# Copyright (c) 1993 - 2026 ARM Limited. All Rights Reserved.
# Use of this Software is subject to the terms and conditions of the
# applicable license agreement with ARM Limited.

# PhyVGen V 11.0.0-beta2
# ARM Version r0p0
# Creation Date: Tue Apr  7 18:10:24 2026


# Memory Configuration:
# ~~~~~~~~~~~~~~~~~~~~~
#  -activity_factor 50 -atf off -back_biasing off -bits 64 -bmux off
# -bus_notation on -check_instname on -diodes on -drive 6 -ema on -frequency
# 1.0 -instname rf64x64 -left_bus_delim "[" -mux 2 -mvt BASE -name_case lower
# -power_gating off -power_type otc -pwr_gnd_rename
# vddpe:VDDPE,vddce:VDDCE,vsse:VSSE -rcols 2 -redundancy off -retention on
# -right_bus_delim "]" -rrows 0 -ser none -site_def off -top_layer m5-m10
# -vmin_assist off -words 64 -wp_size 1 -write_mask on -write_thru off
# 

VERSION 5.8 ;
BUSBITCHARS "[]" ;
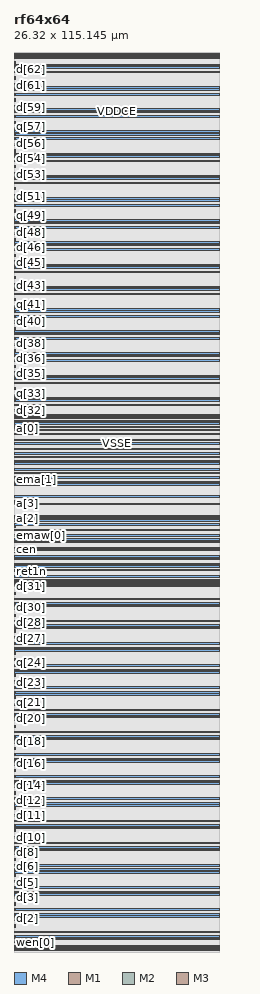
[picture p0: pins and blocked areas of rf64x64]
MACRO rf64x64
	FOREIGN rf64x64 0 0 ;
	SYMMETRY X Y ;
	SIZE 26.32 BY 115.145 ;
	CLASS BLOCK ;
	PIN VDDCE
		USE POWER ;
		DIRECTION INOUT ;
		PORT
			LAYER	M4 ;
			RECT	0 50.525 26.32 50.735 ;
		END

		PORT
			LAYER	M4 ;
			RECT	0 62.375 26.32 62.585 ;
		END

		PORT
			LAYER	M4 ;
			RECT	0 64.235 26.32 64.385 ;
		END

		PORT
			LAYER	M4 ;
			RECT	0 67.84 26.32 67.99 ;
		END

		PORT
			LAYER	M4 ;
			RECT	0 113.045 26.32 113.255 ;
		END

		PORT
			LAYER	M4 ;
			RECT	0 44.49 26.32 44.7 ;
		END

		PORT
			LAYER	M4 ;
			RECT	0 41.65 26.32 41.86 ;
		END

		PORT
			LAYER	M4 ;
			RECT	0 38.81 26.32 39.02 ;
		END

		PORT
			LAYER	M4 ;
			RECT	0 107.365 26.32 107.575 ;
		END

		PORT
			LAYER	M4 ;
			RECT	0 35.97 26.32 36.18 ;
		END

		PORT
			LAYER	M4 ;
			RECT	0 33.13 26.32 33.34 ;
		END

		PORT
			LAYER	M4 ;
			RECT	0 30.29 26.32 30.5 ;
		END

		PORT
			LAYER	M4 ;
			RECT	0 27.45 26.32 27.66 ;
		END

		PORT
			LAYER	M4 ;
			RECT	0 24.61 26.32 24.82 ;
		END

		PORT
			LAYER	M4 ;
			RECT	0 21.77 26.32 21.98 ;
		END

		PORT
			LAYER	M4 ;
			RECT	0 18.93 26.32 19.14 ;
		END

		PORT
			LAYER	M4 ;
			RECT	0 16.09 26.32 16.3 ;
		END

		PORT
			LAYER	M4 ;
			RECT	0 13.25 26.32 13.46 ;
		END

		PORT
			LAYER	M4 ;
			RECT	0 10.41 26.32 10.62 ;
		END

		PORT
			LAYER	M4 ;
			RECT	0 104.525 26.32 104.735 ;
		END

		PORT
			LAYER	M4 ;
			RECT	0 7.57 26.32 7.78 ;
		END

		PORT
			LAYER	M4 ;
			RECT	0 4.73 26.32 4.94 ;
		END

		PORT
			LAYER	M4 ;
			RECT	0 1.89 26.32 2.1 ;
		END

		PORT
			LAYER	M4 ;
			RECT	0 101.685 26.32 101.895 ;
		END

		PORT
			LAYER	M4 ;
			RECT	0 98.845 26.32 99.055 ;
		END

		PORT
			LAYER	M4 ;
			RECT	0 96.005 26.32 96.215 ;
		END

		PORT
			LAYER	M4 ;
			RECT	0 93.165 26.32 93.375 ;
		END

		PORT
			LAYER	M4 ;
			RECT	0 90.325 26.32 90.535 ;
		END

		PORT
			LAYER	M4 ;
			RECT	0 87.485 26.32 87.695 ;
		END

		PORT
			LAYER	M4 ;
			RECT	0 84.645 26.32 84.855 ;
		END

		PORT
			LAYER	M4 ;
			RECT	0 81.805 26.32 82.015 ;
		END

		PORT
			LAYER	M4 ;
			RECT	0 78.965 26.32 79.175 ;
		END

		PORT
			LAYER	M4 ;
			RECT	0 76.125 26.32 76.335 ;
		END

		PORT
			LAYER	M4 ;
			RECT	0 73.285 26.32 73.495 ;
		END

		PORT
			LAYER	M4 ;
			RECT	0 70.445 26.32 70.655 ;
		END

		PORT
			LAYER	M4 ;
			RECT	0 110.205 26.32 110.415 ;
		END

		PORT
			LAYER	M4 ;
			RECT	0 46.795 26.32 46.925 ;
		END

		PORT
			LAYER	M4 ;
			RECT	0 50.225 26.32 50.355 ;
		END

		PORT
			LAYER	M4 ;
			RECT	0 114.325 26.32 114.475 ;
		END

		PORT
			LAYER	M4 ;
			RECT	0 62.755 26.32 62.885 ;
		END

		PORT
			LAYER	M4 ;
			RECT	0 0.67 26.32 0.82 ;
		END

		PORT
			LAYER	M4 ;
			RECT	0 68.63 26.32 68.76 ;
		END

	END VDDCE

	PIN VDDPE
		USE POWER ;
		DIRECTION INOUT ;
		PORT
			LAYER	M4 ;
			RECT	0 48.815 26.32 48.965 ;
		END

		PORT
			LAYER	M4 ;
			RECT	0 49.185 26.32 49.395 ;
		END

		PORT
			LAYER	M4 ;
			RECT	0 52.71 26.32 52.92 ;
		END

		PORT
			LAYER	M4 ;
			RECT	0 53.185 26.32 53.395 ;
		END

		PORT
			LAYER	M4 ;
			RECT	0 54.6 26.32 54.81 ;
		END

		PORT
			LAYER	M4 ;
			RECT	0 55.745 26.32 55.895 ;
		END

		PORT
			LAYER	M4 ;
			RECT	0 58.16 26.32 58.37 ;
		END

		PORT
			LAYER	M4 ;
			RECT	0 59.72 26.32 59.93 ;
		END

		PORT
			LAYER	M4 ;
			RECT	0 60.58 26.32 60.79 ;
		END

		PORT
			LAYER	M4 ;
			RECT	0 63.69 26.32 63.9 ;
		END

		PORT
			LAYER	M4 ;
			RECT	0 66.67 26.32 66.88 ;
		END

		PORT
			LAYER	M4 ;
			RECT	0 67.045 26.32 67.255 ;
		END

		PORT
			LAYER	M4 ;
			RECT	0 112.465 26.32 112.675 ;
		END

		PORT
			LAYER	M4 ;
			RECT	0 45.07 26.32 45.28 ;
		END

		PORT
			LAYER	M4 ;
			RECT	0 42.23 26.32 42.44 ;
		END

		PORT
			LAYER	M4 ;
			RECT	0 39.39 26.32 39.6 ;
		END

		PORT
			LAYER	M4 ;
			RECT	0 36.55 26.32 36.76 ;
		END

		PORT
			LAYER	M4 ;
			RECT	0 33.71 26.32 33.92 ;
		END

		PORT
			LAYER	M4 ;
			RECT	0 106.785 26.32 106.995 ;
		END

		PORT
			LAYER	M4 ;
			RECT	0 30.87 26.32 31.08 ;
		END

		PORT
			LAYER	M4 ;
			RECT	0 28.03 26.32 28.24 ;
		END

		PORT
			LAYER	M4 ;
			RECT	0 25.19 26.32 25.4 ;
		END

		PORT
			LAYER	M4 ;
			RECT	0 22.35 26.32 22.56 ;
		END

		PORT
			LAYER	M4 ;
			RECT	0 19.51 26.32 19.72 ;
		END

		PORT
			LAYER	M4 ;
			RECT	0 16.67 26.32 16.88 ;
		END

		PORT
			LAYER	M4 ;
			RECT	0 13.83 26.32 14.04 ;
		END

		PORT
			LAYER	M4 ;
			RECT	0 10.99 26.32 11.2 ;
		END

		PORT
			LAYER	M4 ;
			RECT	0 8.15 26.32 8.36 ;
		END

		PORT
			LAYER	M4 ;
			RECT	0 5.31 26.32 5.52 ;
		END

		PORT
			LAYER	M4 ;
			RECT	0 103.945 26.32 104.155 ;
		END

		PORT
			LAYER	M4 ;
			RECT	0 2.47 26.32 2.68 ;
		END

		PORT
			LAYER	M4 ;
			RECT	0 101.105 26.32 101.315 ;
		END

		PORT
			LAYER	M4 ;
			RECT	0 98.265 26.32 98.475 ;
		END

		PORT
			LAYER	M4 ;
			RECT	0 95.425 26.32 95.635 ;
		END

		PORT
			LAYER	M4 ;
			RECT	0 92.585 26.32 92.795 ;
		END

		PORT
			LAYER	M4 ;
			RECT	0 89.745 26.32 89.955 ;
		END

		PORT
			LAYER	M4 ;
			RECT	0 86.905 26.32 87.115 ;
		END

		PORT
			LAYER	M4 ;
			RECT	0 84.065 26.32 84.275 ;
		END

		PORT
			LAYER	M4 ;
			RECT	0 81.225 26.32 81.435 ;
		END

		PORT
			LAYER	M4 ;
			RECT	0 78.385 26.32 78.595 ;
		END

		PORT
			LAYER	M4 ;
			RECT	0 75.545 26.32 75.755 ;
		END

		PORT
			LAYER	M4 ;
			RECT	0 72.705 26.32 72.915 ;
		END

		PORT
			LAYER	M4 ;
			RECT	0 69.865 26.32 70.075 ;
		END

		PORT
			LAYER	M4 ;
			RECT	0 109.625 26.32 109.835 ;
		END

		PORT
			LAYER	M4 ;
			RECT	0 114.825 26.32 114.975 ;
		END

		PORT
			LAYER	M4 ;
			RECT	0 47.215 26.32 47.345 ;
		END

		PORT
			LAYER	M4 ;
			RECT	0 51.685 26.32 51.815 ;
		END

		PORT
			LAYER	M4 ;
			RECT	0 0.17 26.32 0.32 ;
		END

		PORT
			LAYER	M4 ;
			RECT	0 60.06 26.32 60.19 ;
		END

		PORT
			LAYER	M4 ;
			RECT	0 68.21 26.32 68.34 ;
		END

	END VDDPE

	PIN VSSE
		USE GROUND ;
		DIRECTION INOUT ;
		PORT
			LAYER	M4 ;
			RECT	0 47.005 26.32 47.135 ;
		END

		PORT
			LAYER	M4 ;
			RECT	0 114.575 26.32 114.725 ;
		END

		PORT
			LAYER	M4 ;
			RECT	0 53.985 26.32 54.115 ;
		END

		PORT
			LAYER	M4 ;
			RECT	0 0.42 26.32 0.57 ;
		END

		PORT
			LAYER	M4 ;
			RECT	0 61.25 26.32 61.38 ;
		END

		PORT
			LAYER	M4 ;
			RECT	0 65.445 26.32 65.575 ;
		END

		PORT
			LAYER	M4 ;
			RECT	0 68.42 26.32 68.55 ;
		END

		PORT
			LAYER	M4 ;
			RECT	0 47.54 26.32 47.67 ;
		END

		PORT
			LAYER	M4 ;
			RECT	0 47.95 26.32 48.16 ;
		END

		PORT
			LAYER	M4 ;
			RECT	0 49.53 26.32 49.74 ;
		END

		PORT
			LAYER	M4 ;
			RECT	0 51.32 26.32 51.47 ;
		END

		PORT
			LAYER	M4 ;
			RECT	0 52.425 26.32 52.575 ;
		END

		PORT
			LAYER	M4 ;
			RECT	0 55.135 26.32 55.285 ;
		END

		PORT
			LAYER	M4 ;
			RECT	0 55.475 26.32 55.625 ;
		END

		PORT
			LAYER	M4 ;
			RECT	0 57.19 26.32 57.4 ;
		END

		PORT
			LAYER	M4 ;
			RECT	0 61.61 26.32 61.82 ;
		END

		PORT
			LAYER	M4 ;
			RECT	0 63.215 26.32 63.425 ;
		END

		PORT
			LAYER	M4 ;
			RECT	0 64.955 26.32 65.165 ;
		END

		PORT
			LAYER	M4 ;
			RECT	0 66.15 26.32 66.36 ;
		END

		PORT
			LAYER	M4 ;
			RECT	0 67.515 26.32 67.725 ;
		END

		PORT
			LAYER	M4 ;
			RECT	0 113.355 26.32 113.565 ;
		END

		PORT
			LAYER	M4 ;
			RECT	0 107.675 26.32 107.885 ;
		END

		PORT
			LAYER	M4 ;
			RECT	0 44.18 26.32 44.39 ;
		END

		PORT
			LAYER	M4 ;
			RECT	0 41.34 26.32 41.55 ;
		END

		PORT
			LAYER	M4 ;
			RECT	0 38.5 26.32 38.71 ;
		END

		PORT
			LAYER	M4 ;
			RECT	0 35.66 26.32 35.87 ;
		END

		PORT
			LAYER	M4 ;
			RECT	0 32.82 26.32 33.03 ;
		END

		PORT
			LAYER	M4 ;
			RECT	0 29.98 26.32 30.19 ;
		END

		PORT
			LAYER	M4 ;
			RECT	0 27.14 26.32 27.35 ;
		END

		PORT
			LAYER	M4 ;
			RECT	0 24.3 26.32 24.51 ;
		END

		PORT
			LAYER	M4 ;
			RECT	0 21.46 26.32 21.67 ;
		END

		PORT
			LAYER	M4 ;
			RECT	0 18.62 26.32 18.83 ;
		END

		PORT
			LAYER	M4 ;
			RECT	0 104.835 26.32 105.045 ;
		END

		PORT
			LAYER	M4 ;
			RECT	0 15.78 26.32 15.99 ;
		END

		PORT
			LAYER	M4 ;
			RECT	0 12.94 26.32 13.15 ;
		END

		PORT
			LAYER	M4 ;
			RECT	0 10.1 26.32 10.31 ;
		END

		PORT
			LAYER	M4 ;
			RECT	0 7.26 26.32 7.47 ;
		END

		PORT
			LAYER	M4 ;
			RECT	0 4.42 26.32 4.63 ;
		END

		PORT
			LAYER	M4 ;
			RECT	0 1.58 26.32 1.79 ;
		END

		PORT
			LAYER	M4 ;
			RECT	0 101.995 26.32 102.205 ;
		END

		PORT
			LAYER	M4 ;
			RECT	0 99.155 26.32 99.365 ;
		END

		PORT
			LAYER	M4 ;
			RECT	0 96.315 26.32 96.525 ;
		END

		PORT
			LAYER	M4 ;
			RECT	0 93.475 26.32 93.685 ;
		END

		PORT
			LAYER	M4 ;
			RECT	0 90.635 26.32 90.845 ;
		END

		PORT
			LAYER	M4 ;
			RECT	0 87.795 26.32 88.005 ;
		END

		PORT
			LAYER	M4 ;
			RECT	0 84.955 26.32 85.165 ;
		END

		PORT
			LAYER	M4 ;
			RECT	0 82.115 26.32 82.325 ;
		END

		PORT
			LAYER	M4 ;
			RECT	0 79.275 26.32 79.485 ;
		END

		PORT
			LAYER	M4 ;
			RECT	0 76.435 26.32 76.645 ;
		END

		PORT
			LAYER	M4 ;
			RECT	0 73.595 26.32 73.805 ;
		END

		PORT
			LAYER	M4 ;
			RECT	0 70.755 26.32 70.965 ;
		END

		PORT
			LAYER	M4 ;
			RECT	0 110.515 26.32 110.725 ;
		END

	END VSSE

	PIN a[0]
		USE SIGNAL ;
		DIRECTION INPUT ;
		SHAPE ABUTMENT ;
		PORT
			LAYER	M1 ;
			RECT	0 66.945 0.25 67.045 ;
			LAYER	M2 ;
			RECT	0 66.945 0.25 67.045 ;
			LAYER	M3 ;
			RECT	0 66.945 0.25 67.045 ;
		END

		ANTENNAGATEAREA 0.014 ;
		ANTENNADIFFAREA 0.018 ;
		ANTENNAPARTIALMETALAREA 0.025 ;
	END a[0]

	PIN a[1]
		USE SIGNAL ;
		DIRECTION INPUT ;
		SHAPE ABUTMENT ;
		PORT
			LAYER	M1 ;
			RECT	0 55.05 0.25 55.15 ;
			LAYER	M2 ;
			RECT	0 55.05 0.25 55.15 ;
			LAYER	M3 ;
			RECT	0 55.05 0.25 55.15 ;
		END

		ANTENNAGATEAREA 0.014 ;
		ANTENNADIFFAREA 0.018 ;
		ANTENNAPARTIALMETALAREA 0.025 ;
	END a[1]

	PIN a[2]
		USE SIGNAL ;
		DIRECTION INPUT ;
		SHAPE ABUTMENT ;
		PORT
			LAYER	M1 ;
			RECT	0 55.45 0.25 55.55 ;
			LAYER	M2 ;
			RECT	0 55.45 0.25 55.55 ;
			LAYER	M3 ;
			RECT	0 55.45 0.25 55.55 ;
		END

		ANTENNAGATEAREA 0.014 ;
		ANTENNADIFFAREA 0.018 ;
		ANTENNAPARTIALMETALAREA 0.025 ;
	END a[2]

	PIN a[3]
		USE SIGNAL ;
		DIRECTION INPUT ;
		SHAPE ABUTMENT ;
		PORT
			LAYER	M1 ;
			RECT	0 57.36 0.25 57.46 ;
			LAYER	M2 ;
			RECT	0 57.36 0.25 57.46 ;
			LAYER	M3 ;
			RECT	0 57.36 0.25 57.46 ;
		END

		ANTENNAGATEAREA 0.014 ;
		ANTENNADIFFAREA 0.018 ;
		ANTENNAPARTIALMETALAREA 0.025 ;
	END a[3]

	PIN a[4]
		USE SIGNAL ;
		DIRECTION INPUT ;
		SHAPE ABUTMENT ;
		PORT
			LAYER	M1 ;
			RECT	0 57.69 0.25 57.79 ;
			LAYER	M2 ;
			RECT	0 57.69 0.25 57.79 ;
			LAYER	M3 ;
			RECT	0 57.69 0.25 57.79 ;
		END

		ANTENNAGATEAREA 0.014 ;
		ANTENNADIFFAREA 0.018 ;
		ANTENNAPARTIALMETALAREA 0.025 ;
	END a[4]

	PIN a[5]
		USE SIGNAL ;
		DIRECTION INPUT ;
		SHAPE ABUTMENT ;
		PORT
			LAYER	M1 ;
			RECT	0 59.795 0.25 59.895 ;
			LAYER	M2 ;
			RECT	0 59.795 0.25 59.895 ;
			LAYER	M3 ;
			RECT	0 59.795 0.25 59.895 ;
		END

		ANTENNAGATEAREA 0.014 ;
		ANTENNADIFFAREA 0.018 ;
		ANTENNAPARTIALMETALAREA 0.025 ;
	END a[5]

	PIN cen
		USE SIGNAL ;
		DIRECTION INPUT ;
		SHAPE ABUTMENT ;
		PORT
			LAYER	M1 ;
			RECT	0 51.46 0.25 51.56 ;
			LAYER	M2 ;
			RECT	0 51.46 0.25 51.56 ;
			LAYER	M3 ;
			RECT	0 51.46 0.25 51.56 ;
		END

		ANTENNAGATEAREA 0.014 ;
		ANTENNADIFFAREA 0.018 ;
		ANTENNAPARTIALMETALAREA 0.025 ;
	END cen

	PIN clk
		USE SIGNAL ;
		DIRECTION INPUT ;
		SHAPE ABUTMENT ;
		PORT
			LAYER	M1 ;
			RECT	0 51.07 0.25 51.17 ;
			LAYER	M2 ;
			RECT	0 51.07 0.25 51.17 ;
			LAYER	M3 ;
			RECT	0 51.07 0.25 51.17 ;
			LAYER	M4 ;
			RECT	0 51.07 0.25 51.17 ;
		END

		ANTENNAGATEAREA 0.014 ;
		ANTENNADIFFAREA 0.018 ;
		ANTENNAPARTIALMETALAREA 0.025 ;
	END clk

	PIN d[0]
		USE SIGNAL ;
		DIRECTION INPUT ;
		SHAPE ABUTMENT ;
		PORT
			LAYER	M1 ;
			RECT	0 1.365 0.25 1.465 ;
			LAYER	M2 ;
			RECT	0 1.365 0.25 1.465 ;
			LAYER	M3 ;
			RECT	0 1.365 0.25 1.465 ;
		END

		ANTENNAGATEAREA 0.014 ;
		ANTENNADIFFAREA 0.018 ;
		ANTENNAPARTIALMETALAREA 0.025 ;
	END d[0]

	PIN d[10]
		USE SIGNAL ;
		DIRECTION INPUT ;
		SHAPE ABUTMENT ;
		PORT
			LAYER	M1 ;
			RECT	0 15.565 0.25 15.665 ;
			LAYER	M2 ;
			RECT	0 15.565 0.25 15.665 ;
			LAYER	M3 ;
			RECT	0 15.565 0.25 15.665 ;
		END

		ANTENNAGATEAREA 0.014 ;
		ANTENNADIFFAREA 0.018 ;
		ANTENNAPARTIALMETALAREA 0.025 ;
	END d[10]

	PIN d[11]
		USE SIGNAL ;
		DIRECTION INPUT ;
		SHAPE ABUTMENT ;
		PORT
			LAYER	M1 ;
			RECT	0 17.355 0.25 17.455 ;
			LAYER	M2 ;
			RECT	0 17.355 0.25 17.455 ;
			LAYER	M3 ;
			RECT	0 17.355 0.25 17.455 ;
		END

		ANTENNAGATEAREA 0.014 ;
		ANTENNADIFFAREA 0.018 ;
		ANTENNAPARTIALMETALAREA 0.025 ;
	END d[11]

	PIN d[12]
		USE SIGNAL ;
		DIRECTION INPUT ;
		SHAPE ABUTMENT ;
		PORT
			LAYER	M1 ;
			RECT	0 18.405 0.25 18.505 ;
			LAYER	M2 ;
			RECT	0 18.405 0.25 18.505 ;
			LAYER	M3 ;
			RECT	0 18.405 0.25 18.505 ;
		END

		ANTENNAGATEAREA 0.014 ;
		ANTENNADIFFAREA 0.018 ;
		ANTENNAPARTIALMETALAREA 0.025 ;
	END d[12]

	PIN d[13]
		USE SIGNAL ;
		DIRECTION INPUT ;
		SHAPE ABUTMENT ;
		PORT
			LAYER	M1 ;
			RECT	0 20.195 0.25 20.295 ;
			LAYER	M2 ;
			RECT	0 20.195 0.25 20.295 ;
			LAYER	M3 ;
			RECT	0 20.195 0.25 20.295 ;
		END

		ANTENNAGATEAREA 0.014 ;
		ANTENNADIFFAREA 0.018 ;
		ANTENNAPARTIALMETALAREA 0.025 ;
	END d[13]

	PIN d[14]
		USE SIGNAL ;
		DIRECTION INPUT ;
		SHAPE ABUTMENT ;
		PORT
			LAYER	M1 ;
			RECT	0 21.245 0.25 21.345 ;
			LAYER	M2 ;
			RECT	0 21.245 0.25 21.345 ;
			LAYER	M3 ;
			RECT	0 21.245 0.25 21.345 ;
		END

		ANTENNAGATEAREA 0.014 ;
		ANTENNADIFFAREA 0.018 ;
		ANTENNAPARTIALMETALAREA 0.025 ;
	END d[14]

	PIN d[15]
		USE SIGNAL ;
		DIRECTION INPUT ;
		SHAPE ABUTMENT ;
		PORT
			LAYER	M1 ;
			RECT	0 23.035 0.25 23.135 ;
			LAYER	M2 ;
			RECT	0 23.035 0.25 23.135 ;
			LAYER	M3 ;
			RECT	0 23.035 0.25 23.135 ;
		END

		ANTENNAGATEAREA 0.014 ;
		ANTENNADIFFAREA 0.018 ;
		ANTENNAPARTIALMETALAREA 0.025 ;
	END d[15]

	PIN d[16]
		USE SIGNAL ;
		DIRECTION INPUT ;
		SHAPE ABUTMENT ;
		PORT
			LAYER	M1 ;
			RECT	0 24.085 0.25 24.185 ;
			LAYER	M2 ;
			RECT	0 24.085 0.25 24.185 ;
			LAYER	M3 ;
			RECT	0 24.085 0.25 24.185 ;
		END

		ANTENNAGATEAREA 0.014 ;
		ANTENNADIFFAREA 0.018 ;
		ANTENNAPARTIALMETALAREA 0.025 ;
	END d[16]

	PIN d[17]
		USE SIGNAL ;
		DIRECTION INPUT ;
		SHAPE ABUTMENT ;
		PORT
			LAYER	M1 ;
			RECT	0 25.875 0.25 25.975 ;
			LAYER	M2 ;
			RECT	0 25.875 0.25 25.975 ;
			LAYER	M3 ;
			RECT	0 25.875 0.25 25.975 ;
		END

		ANTENNAGATEAREA 0.014 ;
		ANTENNADIFFAREA 0.018 ;
		ANTENNAPARTIALMETALAREA 0.025 ;
	END d[17]

	PIN d[18]
		USE SIGNAL ;
		DIRECTION INPUT ;
		SHAPE ABUTMENT ;
		PORT
			LAYER	M1 ;
			RECT	0 26.925 0.25 27.025 ;
			LAYER	M2 ;
			RECT	0 26.925 0.25 27.025 ;
			LAYER	M3 ;
			RECT	0 26.925 0.25 27.025 ;
		END

		ANTENNAGATEAREA 0.014 ;
		ANTENNADIFFAREA 0.018 ;
		ANTENNAPARTIALMETALAREA 0.025 ;
	END d[18]

	PIN d[19]
		USE SIGNAL ;
		DIRECTION INPUT ;
		SHAPE ABUTMENT ;
		PORT
			LAYER	M1 ;
			RECT	0 28.715 0.25 28.815 ;
			LAYER	M2 ;
			RECT	0 28.715 0.25 28.815 ;
			LAYER	M3 ;
			RECT	0 28.715 0.25 28.815 ;
		END

		ANTENNAGATEAREA 0.014 ;
		ANTENNADIFFAREA 0.018 ;
		ANTENNAPARTIALMETALAREA 0.025 ;
	END d[19]

	PIN d[1]
		USE SIGNAL ;
		DIRECTION INPUT ;
		SHAPE ABUTMENT ;
		PORT
			LAYER	M1 ;
			RECT	0 3.155 0.25 3.255 ;
			LAYER	M2 ;
			RECT	0 3.155 0.25 3.255 ;
			LAYER	M3 ;
			RECT	0 3.155 0.25 3.255 ;
		END

		ANTENNAGATEAREA 0.014 ;
		ANTENNADIFFAREA 0.018 ;
		ANTENNAPARTIALMETALAREA 0.025 ;
	END d[1]

	PIN d[20]
		USE SIGNAL ;
		DIRECTION INPUT ;
		SHAPE ABUTMENT ;
		PORT
			LAYER	M1 ;
			RECT	0 29.765 0.25 29.865 ;
			LAYER	M2 ;
			RECT	0 29.765 0.25 29.865 ;
			LAYER	M3 ;
			RECT	0 29.765 0.25 29.865 ;
		END

		ANTENNAGATEAREA 0.014 ;
		ANTENNADIFFAREA 0.018 ;
		ANTENNAPARTIALMETALAREA 0.025 ;
	END d[20]

	PIN d[21]
		USE SIGNAL ;
		DIRECTION INPUT ;
		SHAPE ABUTMENT ;
		PORT
			LAYER	M1 ;
			RECT	0 31.555 0.25 31.655 ;
			LAYER	M2 ;
			RECT	0 31.555 0.25 31.655 ;
			LAYER	M3 ;
			RECT	0 31.555 0.25 31.655 ;
		END

		ANTENNAGATEAREA 0.014 ;
		ANTENNADIFFAREA 0.018 ;
		ANTENNAPARTIALMETALAREA 0.025 ;
	END d[21]

	PIN d[22]
		USE SIGNAL ;
		DIRECTION INPUT ;
		SHAPE ABUTMENT ;
		PORT
			LAYER	M1 ;
			RECT	0 32.605 0.25 32.705 ;
			LAYER	M2 ;
			RECT	0 32.605 0.25 32.705 ;
			LAYER	M3 ;
			RECT	0 32.605 0.25 32.705 ;
		END

		ANTENNAGATEAREA 0.014 ;
		ANTENNADIFFAREA 0.018 ;
		ANTENNAPARTIALMETALAREA 0.025 ;
	END d[22]

	PIN d[23]
		USE SIGNAL ;
		DIRECTION INPUT ;
		SHAPE ABUTMENT ;
		PORT
			LAYER	M1 ;
			RECT	0 34.395 0.25 34.495 ;
			LAYER	M2 ;
			RECT	0 34.395 0.25 34.495 ;
			LAYER	M3 ;
			RECT	0 34.395 0.25 34.495 ;
		END

		ANTENNAGATEAREA 0.014 ;
		ANTENNADIFFAREA 0.018 ;
		ANTENNAPARTIALMETALAREA 0.025 ;
	END d[23]

	PIN d[24]
		USE SIGNAL ;
		DIRECTION INPUT ;
		SHAPE ABUTMENT ;
		PORT
			LAYER	M1 ;
			RECT	0 35.445 0.25 35.545 ;
			LAYER	M2 ;
			RECT	0 35.445 0.25 35.545 ;
			LAYER	M3 ;
			RECT	0 35.445 0.25 35.545 ;
		END

		ANTENNAGATEAREA 0.014 ;
		ANTENNADIFFAREA 0.018 ;
		ANTENNAPARTIALMETALAREA 0.025 ;
	END d[24]

	PIN d[25]
		USE SIGNAL ;
		DIRECTION INPUT ;
		SHAPE ABUTMENT ;
		PORT
			LAYER	M1 ;
			RECT	0 37.235 0.25 37.335 ;
			LAYER	M2 ;
			RECT	0 37.235 0.25 37.335 ;
			LAYER	M3 ;
			RECT	0 37.235 0.25 37.335 ;
		END

		ANTENNAGATEAREA 0.014 ;
		ANTENNADIFFAREA 0.018 ;
		ANTENNAPARTIALMETALAREA 0.025 ;
	END d[25]

	PIN d[26]
		USE SIGNAL ;
		DIRECTION INPUT ;
		SHAPE ABUTMENT ;
		PORT
			LAYER	M1 ;
			RECT	0 38.285 0.25 38.385 ;
			LAYER	M2 ;
			RECT	0 38.285 0.25 38.385 ;
			LAYER	M3 ;
			RECT	0 38.285 0.25 38.385 ;
		END

		ANTENNAGATEAREA 0.014 ;
		ANTENNADIFFAREA 0.018 ;
		ANTENNAPARTIALMETALAREA 0.025 ;
	END d[26]

	PIN d[27]
		USE SIGNAL ;
		DIRECTION INPUT ;
		SHAPE ABUTMENT ;
		PORT
			LAYER	M1 ;
			RECT	0 40.075 0.25 40.175 ;
			LAYER	M2 ;
			RECT	0 40.075 0.25 40.175 ;
			LAYER	M3 ;
			RECT	0 40.075 0.25 40.175 ;
		END

		ANTENNAGATEAREA 0.014 ;
		ANTENNADIFFAREA 0.018 ;
		ANTENNAPARTIALMETALAREA 0.025 ;
	END d[27]

	PIN d[28]
		USE SIGNAL ;
		DIRECTION INPUT ;
		SHAPE ABUTMENT ;
		PORT
			LAYER	M1 ;
			RECT	0 41.125 0.25 41.225 ;
			LAYER	M2 ;
			RECT	0 41.125 0.25 41.225 ;
			LAYER	M3 ;
			RECT	0 41.125 0.25 41.225 ;
		END

		ANTENNAGATEAREA 0.014 ;
		ANTENNADIFFAREA 0.018 ;
		ANTENNAPARTIALMETALAREA 0.025 ;
	END d[28]

	PIN d[29]
		USE SIGNAL ;
		DIRECTION INPUT ;
		SHAPE ABUTMENT ;
		PORT
			LAYER	M1 ;
			RECT	0 42.915 0.25 43.015 ;
			LAYER	M2 ;
			RECT	0 42.915 0.25 43.015 ;
			LAYER	M3 ;
			RECT	0 42.915 0.25 43.015 ;
		END

		ANTENNAGATEAREA 0.014 ;
		ANTENNADIFFAREA 0.018 ;
		ANTENNAPARTIALMETALAREA 0.025 ;
	END d[29]

	PIN d[2]
		USE SIGNAL ;
		DIRECTION INPUT ;
		SHAPE ABUTMENT ;
		PORT
			LAYER	M1 ;
			RECT	0 4.205 0.25 4.305 ;
			LAYER	M2 ;
			RECT	0 4.205 0.25 4.305 ;
			LAYER	M3 ;
			RECT	0 4.205 0.25 4.305 ;
		END

		ANTENNAGATEAREA 0.014 ;
		ANTENNADIFFAREA 0.018 ;
		ANTENNAPARTIALMETALAREA 0.025 ;
	END d[2]

	PIN d[30]
		USE SIGNAL ;
		DIRECTION INPUT ;
		SHAPE ABUTMENT ;
		PORT
			LAYER	M1 ;
			RECT	0 43.965 0.25 44.065 ;
			LAYER	M2 ;
			RECT	0 43.965 0.25 44.065 ;
			LAYER	M3 ;
			RECT	0 43.965 0.25 44.065 ;
		END

		ANTENNAGATEAREA 0.014 ;
		ANTENNADIFFAREA 0.018 ;
		ANTENNAPARTIALMETALAREA 0.025 ;
	END d[30]

	PIN d[31]
		USE SIGNAL ;
		DIRECTION INPUT ;
		SHAPE ABUTMENT ;
		PORT
			LAYER	M1 ;
			RECT	0 45.755 0.25 45.855 ;
			LAYER	M2 ;
			RECT	0 45.755 0.25 45.855 ;
			LAYER	M3 ;
			RECT	0 45.755 0.25 45.855 ;
		END

		ANTENNAGATEAREA 0.014 ;
		ANTENNADIFFAREA 0.018 ;
		ANTENNAPARTIALMETALAREA 0.025 ;
	END d[31]

	PIN d[32]
		USE SIGNAL ;
		DIRECTION INPUT ;
		SHAPE ABUTMENT ;
		PORT
			LAYER	M1 ;
			RECT	0 69.29 0.25 69.39 ;
			LAYER	M2 ;
			RECT	0 69.29 0.25 69.39 ;
			LAYER	M3 ;
			RECT	0 69.29 0.25 69.39 ;
		END

		ANTENNAGATEAREA 0.014 ;
		ANTENNADIFFAREA 0.018 ;
		ANTENNAPARTIALMETALAREA 0.025 ;
	END d[32]

	PIN d[33]
		USE SIGNAL ;
		DIRECTION INPUT ;
		SHAPE ABUTMENT ;
		PORT
			LAYER	M1 ;
			RECT	0 71.08 0.25 71.18 ;
			LAYER	M2 ;
			RECT	0 71.08 0.25 71.18 ;
			LAYER	M3 ;
			RECT	0 71.08 0.25 71.18 ;
		END

		ANTENNAGATEAREA 0.014 ;
		ANTENNADIFFAREA 0.018 ;
		ANTENNAPARTIALMETALAREA 0.025 ;
	END d[33]

	PIN d[34]
		USE SIGNAL ;
		DIRECTION INPUT ;
		SHAPE ABUTMENT ;
		PORT
			LAYER	M1 ;
			RECT	0 72.13 0.25 72.23 ;
			LAYER	M2 ;
			RECT	0 72.13 0.25 72.23 ;
			LAYER	M3 ;
			RECT	0 72.13 0.25 72.23 ;
		END

		ANTENNAGATEAREA 0.014 ;
		ANTENNADIFFAREA 0.018 ;
		ANTENNAPARTIALMETALAREA 0.025 ;
	END d[34]

	PIN d[35]
		USE SIGNAL ;
		DIRECTION INPUT ;
		SHAPE ABUTMENT ;
		PORT
			LAYER	M1 ;
			RECT	0 73.92 0.25 74.02 ;
			LAYER	M2 ;
			RECT	0 73.92 0.25 74.02 ;
			LAYER	M3 ;
			RECT	0 73.92 0.25 74.02 ;
		END

		ANTENNAGATEAREA 0.014 ;
		ANTENNADIFFAREA 0.018 ;
		ANTENNAPARTIALMETALAREA 0.025 ;
	END d[35]

	PIN d[36]
		USE SIGNAL ;
		DIRECTION INPUT ;
		SHAPE ABUTMENT ;
		PORT
			LAYER	M1 ;
			RECT	0 74.97 0.25 75.07 ;
			LAYER	M2 ;
			RECT	0 74.97 0.25 75.07 ;
			LAYER	M3 ;
			RECT	0 74.97 0.25 75.07 ;
		END

		ANTENNAGATEAREA 0.014 ;
		ANTENNADIFFAREA 0.018 ;
		ANTENNAPARTIALMETALAREA 0.025 ;
	END d[36]

	PIN d[37]
		USE SIGNAL ;
		DIRECTION INPUT ;
		SHAPE ABUTMENT ;
		PORT
			LAYER	M1 ;
			RECT	0 76.76 0.25 76.86 ;
			LAYER	M2 ;
			RECT	0 76.76 0.25 76.86 ;
			LAYER	M3 ;
			RECT	0 76.76 0.25 76.86 ;
		END

		ANTENNAGATEAREA 0.014 ;
		ANTENNADIFFAREA 0.018 ;
		ANTENNAPARTIALMETALAREA 0.025 ;
	END d[37]

	PIN d[38]
		USE SIGNAL ;
		DIRECTION INPUT ;
		SHAPE ABUTMENT ;
		PORT
			LAYER	M1 ;
			RECT	0 77.81 0.25 77.91 ;
			LAYER	M2 ;
			RECT	0 77.81 0.25 77.91 ;
			LAYER	M3 ;
			RECT	0 77.81 0.25 77.91 ;
		END

		ANTENNAGATEAREA 0.014 ;
		ANTENNADIFFAREA 0.018 ;
		ANTENNAPARTIALMETALAREA 0.025 ;
	END d[38]

	PIN d[39]
		USE SIGNAL ;
		DIRECTION INPUT ;
		SHAPE ABUTMENT ;
		PORT
			LAYER	M1 ;
			RECT	0 79.6 0.25 79.7 ;
			LAYER	M2 ;
			RECT	0 79.6 0.25 79.7 ;
			LAYER	M3 ;
			RECT	0 79.6 0.25 79.7 ;
		END

		ANTENNAGATEAREA 0.014 ;
		ANTENNADIFFAREA 0.018 ;
		ANTENNAPARTIALMETALAREA 0.025 ;
	END d[39]

	PIN d[3]
		USE SIGNAL ;
		DIRECTION INPUT ;
		SHAPE ABUTMENT ;
		PORT
			LAYER	M1 ;
			RECT	0 5.995 0.25 6.095 ;
			LAYER	M2 ;
			RECT	0 5.995 0.25 6.095 ;
			LAYER	M3 ;
			RECT	0 5.995 0.25 6.095 ;
		END

		ANTENNAGATEAREA 0.014 ;
		ANTENNADIFFAREA 0.018 ;
		ANTENNAPARTIALMETALAREA 0.025 ;
	END d[3]

	PIN d[40]
		USE SIGNAL ;
		DIRECTION INPUT ;
		SHAPE ABUTMENT ;
		PORT
			LAYER	M1 ;
			RECT	0 80.65 0.25 80.75 ;
			LAYER	M2 ;
			RECT	0 80.65 0.25 80.75 ;
			LAYER	M3 ;
			RECT	0 80.65 0.25 80.75 ;
		END

		ANTENNAGATEAREA 0.014 ;
		ANTENNADIFFAREA 0.018 ;
		ANTENNAPARTIALMETALAREA 0.025 ;
	END d[40]

	PIN d[41]
		USE SIGNAL ;
		DIRECTION INPUT ;
		SHAPE ABUTMENT ;
		PORT
			LAYER	M1 ;
			RECT	0 82.44 0.25 82.54 ;
			LAYER	M2 ;
			RECT	0 82.44 0.25 82.54 ;
			LAYER	M3 ;
			RECT	0 82.44 0.25 82.54 ;
		END

		ANTENNAGATEAREA 0.014 ;
		ANTENNADIFFAREA 0.018 ;
		ANTENNAPARTIALMETALAREA 0.025 ;
	END d[41]

	PIN d[42]
		USE SIGNAL ;
		DIRECTION INPUT ;
		SHAPE ABUTMENT ;
		PORT
			LAYER	M1 ;
			RECT	0 83.49 0.25 83.59 ;
			LAYER	M2 ;
			RECT	0 83.49 0.25 83.59 ;
			LAYER	M3 ;
			RECT	0 83.49 0.25 83.59 ;
		END

		ANTENNAGATEAREA 0.014 ;
		ANTENNADIFFAREA 0.018 ;
		ANTENNAPARTIALMETALAREA 0.025 ;
	END d[42]

	PIN d[43]
		USE SIGNAL ;
		DIRECTION INPUT ;
		SHAPE ABUTMENT ;
		PORT
			LAYER	M1 ;
			RECT	0 85.28 0.25 85.38 ;
			LAYER	M2 ;
			RECT	0 85.28 0.25 85.38 ;
			LAYER	M3 ;
			RECT	0 85.28 0.25 85.38 ;
		END

		ANTENNAGATEAREA 0.014 ;
		ANTENNADIFFAREA 0.018 ;
		ANTENNAPARTIALMETALAREA 0.025 ;
	END d[43]

	PIN d[44]
		USE SIGNAL ;
		DIRECTION INPUT ;
		SHAPE ABUTMENT ;
		PORT
			LAYER	M1 ;
			RECT	0 86.33 0.25 86.43 ;
			LAYER	M2 ;
			RECT	0 86.33 0.25 86.43 ;
			LAYER	M3 ;
			RECT	0 86.33 0.25 86.43 ;
		END

		ANTENNAGATEAREA 0.014 ;
		ANTENNADIFFAREA 0.018 ;
		ANTENNAPARTIALMETALAREA 0.025 ;
	END d[44]

	PIN d[45]
		USE SIGNAL ;
		DIRECTION INPUT ;
		SHAPE ABUTMENT ;
		PORT
			LAYER	M1 ;
			RECT	0 88.12 0.25 88.22 ;
			LAYER	M2 ;
			RECT	0 88.12 0.25 88.22 ;
			LAYER	M3 ;
			RECT	0 88.12 0.25 88.22 ;
		END

		ANTENNAGATEAREA 0.014 ;
		ANTENNADIFFAREA 0.018 ;
		ANTENNAPARTIALMETALAREA 0.025 ;
	END d[45]

	PIN d[46]
		USE SIGNAL ;
		DIRECTION INPUT ;
		SHAPE ABUTMENT ;
		PORT
			LAYER	M1 ;
			RECT	0 89.17 0.25 89.27 ;
			LAYER	M2 ;
			RECT	0 89.17 0.25 89.27 ;
			LAYER	M3 ;
			RECT	0 89.17 0.25 89.27 ;
		END

		ANTENNAGATEAREA 0.014 ;
		ANTENNADIFFAREA 0.018 ;
		ANTENNAPARTIALMETALAREA 0.025 ;
	END d[46]

	PIN d[47]
		USE SIGNAL ;
		DIRECTION INPUT ;
		SHAPE ABUTMENT ;
		PORT
			LAYER	M1 ;
			RECT	0 90.96 0.25 91.06 ;
			LAYER	M2 ;
			RECT	0 90.96 0.25 91.06 ;
			LAYER	M3 ;
			RECT	0 90.96 0.25 91.06 ;
		END

		ANTENNAGATEAREA 0.014 ;
		ANTENNADIFFAREA 0.018 ;
		ANTENNAPARTIALMETALAREA 0.025 ;
	END d[47]

	PIN d[48]
		USE SIGNAL ;
		DIRECTION INPUT ;
		SHAPE ABUTMENT ;
		PORT
			LAYER	M1 ;
			RECT	0 92.01 0.25 92.11 ;
			LAYER	M2 ;
			RECT	0 92.01 0.25 92.11 ;
			LAYER	M3 ;
			RECT	0 92.01 0.25 92.11 ;
		END

		ANTENNAGATEAREA 0.014 ;
		ANTENNADIFFAREA 0.018 ;
		ANTENNAPARTIALMETALAREA 0.025 ;
	END d[48]

	PIN d[49]
		USE SIGNAL ;
		DIRECTION INPUT ;
		SHAPE ABUTMENT ;
		PORT
			LAYER	M1 ;
			RECT	0 93.8 0.25 93.9 ;
			LAYER	M2 ;
			RECT	0 93.8 0.25 93.9 ;
			LAYER	M3 ;
			RECT	0 93.8 0.25 93.9 ;
		END

		ANTENNAGATEAREA 0.014 ;
		ANTENNADIFFAREA 0.018 ;
		ANTENNAPARTIALMETALAREA 0.025 ;
	END d[49]

	PIN d[4]
		USE SIGNAL ;
		DIRECTION INPUT ;
		SHAPE ABUTMENT ;
		PORT
			LAYER	M1 ;
			RECT	0 7.045 0.25 7.145 ;
			LAYER	M2 ;
			RECT	0 7.045 0.25 7.145 ;
			LAYER	M3 ;
			RECT	0 7.045 0.25 7.145 ;
		END

		ANTENNAGATEAREA 0.014 ;
		ANTENNADIFFAREA 0.018 ;
		ANTENNAPARTIALMETALAREA 0.025 ;
	END d[4]

	PIN d[50]
		USE SIGNAL ;
		DIRECTION INPUT ;
		SHAPE ABUTMENT ;
		PORT
			LAYER	M1 ;
			RECT	0 94.85 0.25 94.95 ;
			LAYER	M2 ;
			RECT	0 94.85 0.25 94.95 ;
			LAYER	M3 ;
			RECT	0 94.85 0.25 94.95 ;
		END

		ANTENNAGATEAREA 0.014 ;
		ANTENNADIFFAREA 0.018 ;
		ANTENNAPARTIALMETALAREA 0.025 ;
	END d[50]

	PIN d[51]
		USE SIGNAL ;
		DIRECTION INPUT ;
		SHAPE ABUTMENT ;
		PORT
			LAYER	M1 ;
			RECT	0 96.64 0.25 96.74 ;
			LAYER	M2 ;
			RECT	0 96.64 0.25 96.74 ;
			LAYER	M3 ;
			RECT	0 96.64 0.25 96.74 ;
		END

		ANTENNAGATEAREA 0.014 ;
		ANTENNADIFFAREA 0.018 ;
		ANTENNAPARTIALMETALAREA 0.025 ;
	END d[51]

	PIN d[52]
		USE SIGNAL ;
		DIRECTION INPUT ;
		SHAPE ABUTMENT ;
		PORT
			LAYER	M1 ;
			RECT	0 97.69 0.25 97.79 ;
			LAYER	M2 ;
			RECT	0 97.69 0.25 97.79 ;
			LAYER	M3 ;
			RECT	0 97.69 0.25 97.79 ;
		END

		ANTENNAGATEAREA 0.014 ;
		ANTENNADIFFAREA 0.018 ;
		ANTENNAPARTIALMETALAREA 0.025 ;
	END d[52]

	PIN d[53]
		USE SIGNAL ;
		DIRECTION INPUT ;
		SHAPE ABUTMENT ;
		PORT
			LAYER	M1 ;
			RECT	0 99.48 0.25 99.58 ;
			LAYER	M2 ;
			RECT	0 99.48 0.25 99.58 ;
			LAYER	M3 ;
			RECT	0 99.48 0.25 99.58 ;
		END

		ANTENNAGATEAREA 0.014 ;
		ANTENNADIFFAREA 0.018 ;
		ANTENNAPARTIALMETALAREA 0.025 ;
	END d[53]

	PIN d[54]
		USE SIGNAL ;
		DIRECTION INPUT ;
		SHAPE ABUTMENT ;
		PORT
			LAYER	M1 ;
			RECT	0 100.53 0.25 100.63 ;
			LAYER	M2 ;
			RECT	0 100.53 0.25 100.63 ;
			LAYER	M3 ;
			RECT	0 100.53 0.25 100.63 ;
		END

		ANTENNAGATEAREA 0.014 ;
		ANTENNADIFFAREA 0.018 ;
		ANTENNAPARTIALMETALAREA 0.025 ;
	END d[54]

	PIN d[55]
		USE SIGNAL ;
		DIRECTION INPUT ;
		SHAPE ABUTMENT ;
		PORT
			LAYER	M1 ;
			RECT	0 102.32 0.25 102.42 ;
			LAYER	M2 ;
			RECT	0 102.32 0.25 102.42 ;
			LAYER	M3 ;
			RECT	0 102.32 0.25 102.42 ;
		END

		ANTENNAGATEAREA 0.014 ;
		ANTENNADIFFAREA 0.018 ;
		ANTENNAPARTIALMETALAREA 0.025 ;
	END d[55]

	PIN d[56]
		USE SIGNAL ;
		DIRECTION INPUT ;
		SHAPE ABUTMENT ;
		PORT
			LAYER	M1 ;
			RECT	0 103.37 0.25 103.47 ;
			LAYER	M2 ;
			RECT	0 103.37 0.25 103.47 ;
			LAYER	M3 ;
			RECT	0 103.37 0.25 103.47 ;
		END

		ANTENNAGATEAREA 0.014 ;
		ANTENNADIFFAREA 0.018 ;
		ANTENNAPARTIALMETALAREA 0.025 ;
	END d[56]

	PIN d[57]
		USE SIGNAL ;
		DIRECTION INPUT ;
		SHAPE ABUTMENT ;
		PORT
			LAYER	M1 ;
			RECT	0 105.16 0.25 105.26 ;
			LAYER	M2 ;
			RECT	0 105.16 0.25 105.26 ;
			LAYER	M3 ;
			RECT	0 105.16 0.25 105.26 ;
		END

		ANTENNAGATEAREA 0.014 ;
		ANTENNADIFFAREA 0.018 ;
		ANTENNAPARTIALMETALAREA 0.025 ;
	END d[57]

	PIN d[58]
		USE SIGNAL ;
		DIRECTION INPUT ;
		SHAPE ABUTMENT ;
		PORT
			LAYER	M1 ;
			RECT	0 106.21 0.25 106.31 ;
			LAYER	M2 ;
			RECT	0 106.21 0.25 106.31 ;
			LAYER	M3 ;
			RECT	0 106.21 0.25 106.31 ;
		END

		ANTENNAGATEAREA 0.014 ;
		ANTENNADIFFAREA 0.018 ;
		ANTENNAPARTIALMETALAREA 0.025 ;
	END d[58]

	PIN d[59]
		USE SIGNAL ;
		DIRECTION INPUT ;
		SHAPE ABUTMENT ;
		PORT
			LAYER	M1 ;
			RECT	0 108 0.25 108.1 ;
			LAYER	M2 ;
			RECT	0 108 0.25 108.1 ;
			LAYER	M3 ;
			RECT	0 108 0.25 108.1 ;
		END

		ANTENNAGATEAREA 0.014 ;
		ANTENNADIFFAREA 0.018 ;
		ANTENNAPARTIALMETALAREA 0.025 ;
	END d[59]

	PIN d[5]
		USE SIGNAL ;
		DIRECTION INPUT ;
		SHAPE ABUTMENT ;
		PORT
			LAYER	M1 ;
			RECT	0 8.835 0.25 8.935 ;
			LAYER	M2 ;
			RECT	0 8.835 0.25 8.935 ;
			LAYER	M3 ;
			RECT	0 8.835 0.25 8.935 ;
		END

		ANTENNAGATEAREA 0.014 ;
		ANTENNADIFFAREA 0.018 ;
		ANTENNAPARTIALMETALAREA 0.025 ;
	END d[5]

	PIN d[60]
		USE SIGNAL ;
		DIRECTION INPUT ;
		SHAPE ABUTMENT ;
		PORT
			LAYER	M1 ;
			RECT	0 109.05 0.25 109.15 ;
			LAYER	M2 ;
			RECT	0 109.05 0.25 109.15 ;
			LAYER	M3 ;
			RECT	0 109.05 0.25 109.15 ;
		END

		ANTENNAGATEAREA 0.014 ;
		ANTENNADIFFAREA 0.018 ;
		ANTENNAPARTIALMETALAREA 0.025 ;
	END d[60]

	PIN d[61]
		USE SIGNAL ;
		DIRECTION INPUT ;
		SHAPE ABUTMENT ;
		PORT
			LAYER	M1 ;
			RECT	0 110.84 0.25 110.94 ;
			LAYER	M2 ;
			RECT	0 110.84 0.25 110.94 ;
			LAYER	M3 ;
			RECT	0 110.84 0.25 110.94 ;
		END

		ANTENNAGATEAREA 0.014 ;
		ANTENNADIFFAREA 0.018 ;
		ANTENNAPARTIALMETALAREA 0.025 ;
	END d[61]

	PIN d[62]
		USE SIGNAL ;
		DIRECTION INPUT ;
		SHAPE ABUTMENT ;
		PORT
			LAYER	M1 ;
			RECT	0 111.89 0.25 111.99 ;
			LAYER	M2 ;
			RECT	0 111.89 0.25 111.99 ;
			LAYER	M3 ;
			RECT	0 111.89 0.25 111.99 ;
		END

		ANTENNAGATEAREA 0.014 ;
		ANTENNADIFFAREA 0.018 ;
		ANTENNAPARTIALMETALAREA 0.025 ;
	END d[62]

	PIN d[63]
		USE SIGNAL ;
		DIRECTION INPUT ;
		SHAPE ABUTMENT ;
		PORT
			LAYER	M1 ;
			RECT	0 113.68 0.25 113.78 ;
			LAYER	M2 ;
			RECT	0 113.68 0.25 113.78 ;
			LAYER	M3 ;
			RECT	0 113.68 0.25 113.78 ;
		END

		ANTENNAGATEAREA 0.014 ;
		ANTENNADIFFAREA 0.018 ;
		ANTENNAPARTIALMETALAREA 0.025 ;
	END d[63]

	PIN d[6]
		USE SIGNAL ;
		DIRECTION INPUT ;
		SHAPE ABUTMENT ;
		PORT
			LAYER	M1 ;
			RECT	0 9.885 0.25 9.985 ;
			LAYER	M2 ;
			RECT	0 9.885 0.25 9.985 ;
			LAYER	M3 ;
			RECT	0 9.885 0.25 9.985 ;
		END

		ANTENNAGATEAREA 0.014 ;
		ANTENNADIFFAREA 0.018 ;
		ANTENNAPARTIALMETALAREA 0.025 ;
	END d[6]

	PIN d[7]
		USE SIGNAL ;
		DIRECTION INPUT ;
		SHAPE ABUTMENT ;
		PORT
			LAYER	M1 ;
			RECT	0 11.675 0.25 11.775 ;
			LAYER	M2 ;
			RECT	0 11.675 0.25 11.775 ;
			LAYER	M3 ;
			RECT	0 11.675 0.25 11.775 ;
		END

		ANTENNAGATEAREA 0.014 ;
		ANTENNADIFFAREA 0.018 ;
		ANTENNAPARTIALMETALAREA 0.025 ;
	END d[7]

	PIN d[8]
		USE SIGNAL ;
		DIRECTION INPUT ;
		SHAPE ABUTMENT ;
		PORT
			LAYER	M1 ;
			RECT	0 12.725 0.25 12.825 ;
			LAYER	M2 ;
			RECT	0 12.725 0.25 12.825 ;
			LAYER	M3 ;
			RECT	0 12.725 0.25 12.825 ;
		END

		ANTENNAGATEAREA 0.014 ;
		ANTENNADIFFAREA 0.018 ;
		ANTENNAPARTIALMETALAREA 0.025 ;
	END d[8]

	PIN d[9]
		USE SIGNAL ;
		DIRECTION INPUT ;
		SHAPE ABUTMENT ;
		PORT
			LAYER	M1 ;
			RECT	0 14.515 0.25 14.615 ;
			LAYER	M2 ;
			RECT	0 14.515 0.25 14.615 ;
			LAYER	M3 ;
			RECT	0 14.515 0.25 14.615 ;
		END

		ANTENNAGATEAREA 0.014 ;
		ANTENNADIFFAREA 0.018 ;
		ANTENNAPARTIALMETALAREA 0.025 ;
	END d[9]

	PIN ema[0]
		USE SIGNAL ;
		DIRECTION INPUT ;
		SHAPE ABUTMENT ;
		PORT
			LAYER	M1 ;
			RECT	0 60.665 0.25 60.765 ;
			LAYER	M2 ;
			RECT	0 60.665 0.25 60.765 ;
			LAYER	M3 ;
			RECT	0 60.665 0.25 60.765 ;
		END

		ANTENNAGATEAREA 0.014 ;
		ANTENNADIFFAREA 0.018 ;
		ANTENNAPARTIALMETALAREA 0.025 ;
	END ema[0]

	PIN ema[1]
		USE SIGNAL ;
		DIRECTION INPUT ;
		SHAPE ABUTMENT ;
		PORT
			LAYER	M1 ;
			RECT	0 60.465 0.25 60.565 ;
			LAYER	M2 ;
			RECT	0 60.465 0.25 60.565 ;
			LAYER	M3 ;
			RECT	0 60.465 0.25 60.565 ;
		END

		ANTENNAGATEAREA 0.014 ;
		ANTENNADIFFAREA 0.018 ;
		ANTENNAPARTIALMETALAREA 0.025 ;
	END ema[1]

	PIN ema[2]
		USE SIGNAL ;
		DIRECTION INPUT ;
		SHAPE ABUTMENT ;
		PORT
			LAYER	M1 ;
			RECT	0 60.265 0.25 60.365 ;
			LAYER	M2 ;
			RECT	0 60.265 0.25 60.365 ;
			LAYER	M3 ;
			RECT	0 60.265 0.25 60.365 ;
		END

		ANTENNAGATEAREA 0.014 ;
		ANTENNADIFFAREA 0.018 ;
		ANTENNAPARTIALMETALAREA 0.025 ;
	END ema[2]

	PIN emas
		USE SIGNAL ;
		DIRECTION INPUT ;
		SHAPE ABUTMENT ;
		PORT
			LAYER	M1 ;
			RECT	0 67.32 0.25 67.42 ;
			LAYER	M2 ;
			RECT	0 67.32 0.25 67.42 ;
			LAYER	M3 ;
			RECT	0 67.32 0.25 67.42 ;
		END

		ANTENNAGATEAREA 0.014 ;
		ANTENNADIFFAREA 0.018 ;
		ANTENNAPARTIALMETALAREA 0.025 ;
	END emas

	PIN emaw[0]
		USE SIGNAL ;
		DIRECTION INPUT ;
		SHAPE ABUTMENT ;
		PORT
			LAYER	M2 ;
			RECT	0 54.255 0.25 54.355 ;
			LAYER	M3 ;
			RECT	0 54.255 0.25 54.355 ;
		END

		ANTENNAGATEAREA 0.014 ;
		ANTENNADIFFAREA 0.018 ;
		ANTENNAPARTIALMETALAREA 0.025 ;
	END emaw[0]

	PIN emaw[1]
		USE SIGNAL ;
		DIRECTION INPUT ;
		SHAPE ABUTMENT ;
		PORT
			LAYER	M1 ;
			RECT	0 54.45 0.25 54.55 ;
			LAYER	M2 ;
			RECT	0 54.45 0.25 54.55 ;
			LAYER	M3 ;
			RECT	0 54.45 0.25 54.55 ;
		END

		ANTENNAGATEAREA 0.014 ;
		ANTENNADIFFAREA 0.018 ;
		ANTENNAPARTIALMETALAREA 0.025 ;
	END emaw[1]

	PIN gwen
		USE SIGNAL ;
		DIRECTION INPUT ;
		SHAPE ABUTMENT ;
		PORT
			LAYER	M1 ;
			RECT	0 52.585 0.25 52.685 ;
			LAYER	M2 ;
			RECT	0 52.585 0.25 52.685 ;
			LAYER	M3 ;
			RECT	0 52.585 0.25 52.685 ;
		END

		ANTENNAGATEAREA 0.014 ;
		ANTENNADIFFAREA 0.018 ;
		ANTENNAPARTIALMETALAREA 0.025 ;
	END gwen

	PIN q[0]
		USE SIGNAL ;
		DIRECTION OUTPUT ;
		SHAPE ABUTMENT ;
		PORT
			LAYER	M1 ;
			RECT	0 1.995 0.25 2.095 ;
			LAYER	M2 ;
			RECT	0 1.995 0.25 2.095 ;
			LAYER	M3 ;
			RECT	0 1.995 0.25 2.095 ;
		END

		ANTENNADIFFAREA 0.018 ;
		ANTENNAPARTIALMETALAREA 0.025 ;
	END q[0]

	PIN q[10]
		USE SIGNAL ;
		DIRECTION OUTPUT ;
		SHAPE ABUTMENT ;
		PORT
			LAYER	M1 ;
			RECT	0 16.195 0.25 16.295 ;
			LAYER	M2 ;
			RECT	0 16.195 0.25 16.295 ;
			LAYER	M3 ;
			RECT	0 16.195 0.25 16.295 ;
		END

		ANTENNADIFFAREA 0.018 ;
		ANTENNAPARTIALMETALAREA 0.025 ;
	END q[10]

	PIN q[11]
		USE SIGNAL ;
		DIRECTION OUTPUT ;
		SHAPE ABUTMENT ;
		PORT
			LAYER	M1 ;
			RECT	0 16.725 0.25 16.825 ;
			LAYER	M2 ;
			RECT	0 16.725 0.25 16.825 ;
			LAYER	M3 ;
			RECT	0 16.725 0.25 16.825 ;
		END

		ANTENNADIFFAREA 0.018 ;
		ANTENNAPARTIALMETALAREA 0.025 ;
	END q[11]

	PIN q[12]
		USE SIGNAL ;
		DIRECTION OUTPUT ;
		SHAPE ABUTMENT ;
		PORT
			LAYER	M1 ;
			RECT	0 19.035 0.25 19.135 ;
			LAYER	M2 ;
			RECT	0 19.035 0.25 19.135 ;
			LAYER	M3 ;
			RECT	0 19.035 0.25 19.135 ;
		END

		ANTENNADIFFAREA 0.018 ;
		ANTENNAPARTIALMETALAREA 0.025 ;
	END q[12]

	PIN q[13]
		USE SIGNAL ;
		DIRECTION OUTPUT ;
		SHAPE ABUTMENT ;
		PORT
			LAYER	M1 ;
			RECT	0 19.565 0.25 19.665 ;
			LAYER	M2 ;
			RECT	0 19.565 0.25 19.665 ;
			LAYER	M3 ;
			RECT	0 19.565 0.25 19.665 ;
		END

		ANTENNADIFFAREA 0.018 ;
		ANTENNAPARTIALMETALAREA 0.025 ;
	END q[13]

	PIN q[14]
		USE SIGNAL ;
		DIRECTION OUTPUT ;
		SHAPE ABUTMENT ;
		PORT
			LAYER	M1 ;
			RECT	0 21.875 0.25 21.975 ;
			LAYER	M2 ;
			RECT	0 21.875 0.25 21.975 ;
			LAYER	M3 ;
			RECT	0 21.875 0.25 21.975 ;
		END

		ANTENNADIFFAREA 0.018 ;
		ANTENNAPARTIALMETALAREA 0.025 ;
	END q[14]

	PIN q[15]
		USE SIGNAL ;
		DIRECTION OUTPUT ;
		SHAPE ABUTMENT ;
		PORT
			LAYER	M1 ;
			RECT	0 22.405 0.25 22.505 ;
			LAYER	M2 ;
			RECT	0 22.405 0.25 22.505 ;
			LAYER	M3 ;
			RECT	0 22.405 0.25 22.505 ;
		END

		ANTENNADIFFAREA 0.018 ;
		ANTENNAPARTIALMETALAREA 0.025 ;
	END q[15]

	PIN q[16]
		USE SIGNAL ;
		DIRECTION OUTPUT ;
		SHAPE ABUTMENT ;
		PORT
			LAYER	M1 ;
			RECT	0 24.715 0.25 24.815 ;
			LAYER	M2 ;
			RECT	0 24.715 0.25 24.815 ;
			LAYER	M3 ;
			RECT	0 24.715 0.25 24.815 ;
		END

		ANTENNADIFFAREA 0.018 ;
		ANTENNAPARTIALMETALAREA 0.025 ;
	END q[16]

	PIN q[17]
		USE SIGNAL ;
		DIRECTION OUTPUT ;
		SHAPE ABUTMENT ;
		PORT
			LAYER	M1 ;
			RECT	0 25.245 0.25 25.345 ;
			LAYER	M2 ;
			RECT	0 25.245 0.25 25.345 ;
			LAYER	M3 ;
			RECT	0 25.245 0.25 25.345 ;
		END

		ANTENNADIFFAREA 0.018 ;
		ANTENNAPARTIALMETALAREA 0.025 ;
	END q[17]

	PIN q[18]
		USE SIGNAL ;
		DIRECTION OUTPUT ;
		SHAPE ABUTMENT ;
		PORT
			LAYER	M1 ;
			RECT	0 27.555 0.25 27.655 ;
			LAYER	M2 ;
			RECT	0 27.555 0.25 27.655 ;
			LAYER	M3 ;
			RECT	0 27.555 0.25 27.655 ;
		END

		ANTENNADIFFAREA 0.018 ;
		ANTENNAPARTIALMETALAREA 0.025 ;
	END q[18]

	PIN q[19]
		USE SIGNAL ;
		DIRECTION OUTPUT ;
		SHAPE ABUTMENT ;
		PORT
			LAYER	M1 ;
			RECT	0 28.085 0.25 28.185 ;
			LAYER	M2 ;
			RECT	0 28.085 0.25 28.185 ;
			LAYER	M3 ;
			RECT	0 28.085 0.25 28.185 ;
		END

		ANTENNADIFFAREA 0.018 ;
		ANTENNAPARTIALMETALAREA 0.025 ;
	END q[19]

	PIN q[1]
		USE SIGNAL ;
		DIRECTION OUTPUT ;
		SHAPE ABUTMENT ;
		PORT
			LAYER	M1 ;
			RECT	0 2.525 0.25 2.625 ;
			LAYER	M2 ;
			RECT	0 2.525 0.25 2.625 ;
			LAYER	M3 ;
			RECT	0 2.525 0.25 2.625 ;
		END

		ANTENNADIFFAREA 0.018 ;
		ANTENNAPARTIALMETALAREA 0.025 ;
	END q[1]

	PIN q[20]
		USE SIGNAL ;
		DIRECTION OUTPUT ;
		SHAPE ABUTMENT ;
		PORT
			LAYER	M1 ;
			RECT	0 30.395 0.25 30.495 ;
			LAYER	M2 ;
			RECT	0 30.395 0.25 30.495 ;
			LAYER	M3 ;
			RECT	0 30.395 0.25 30.495 ;
		END

		ANTENNADIFFAREA 0.018 ;
		ANTENNAPARTIALMETALAREA 0.025 ;
	END q[20]

	PIN q[21]
		USE SIGNAL ;
		DIRECTION OUTPUT ;
		SHAPE ABUTMENT ;
		PORT
			LAYER	M1 ;
			RECT	0 30.925 0.25 31.025 ;
			LAYER	M2 ;
			RECT	0 30.925 0.25 31.025 ;
			LAYER	M3 ;
			RECT	0 30.925 0.25 31.025 ;
		END

		ANTENNADIFFAREA 0.018 ;
		ANTENNAPARTIALMETALAREA 0.025 ;
	END q[21]

	PIN q[22]
		USE SIGNAL ;
		DIRECTION OUTPUT ;
		SHAPE ABUTMENT ;
		PORT
			LAYER	M1 ;
			RECT	0 33.235 0.25 33.335 ;
			LAYER	M2 ;
			RECT	0 33.235 0.25 33.335 ;
			LAYER	M3 ;
			RECT	0 33.235 0.25 33.335 ;
		END

		ANTENNADIFFAREA 0.018 ;
		ANTENNAPARTIALMETALAREA 0.025 ;
	END q[22]

	PIN q[23]
		USE SIGNAL ;
		DIRECTION OUTPUT ;
		SHAPE ABUTMENT ;
		PORT
			LAYER	M1 ;
			RECT	0 33.765 0.25 33.865 ;
			LAYER	M2 ;
			RECT	0 33.765 0.25 33.865 ;
			LAYER	M3 ;
			RECT	0 33.765 0.25 33.865 ;
		END

		ANTENNADIFFAREA 0.018 ;
		ANTENNAPARTIALMETALAREA 0.025 ;
	END q[23]

	PIN q[24]
		USE SIGNAL ;
		DIRECTION OUTPUT ;
		SHAPE ABUTMENT ;
		PORT
			LAYER	M1 ;
			RECT	0 36.075 0.25 36.175 ;
			LAYER	M2 ;
			RECT	0 36.075 0.25 36.175 ;
			LAYER	M3 ;
			RECT	0 36.075 0.25 36.175 ;
		END

		ANTENNADIFFAREA 0.018 ;
		ANTENNAPARTIALMETALAREA 0.025 ;
	END q[24]

	PIN q[25]
		USE SIGNAL ;
		DIRECTION OUTPUT ;
		SHAPE ABUTMENT ;
		PORT
			LAYER	M1 ;
			RECT	0 36.605 0.25 36.705 ;
			LAYER	M2 ;
			RECT	0 36.605 0.25 36.705 ;
			LAYER	M3 ;
			RECT	0 36.605 0.25 36.705 ;
		END

		ANTENNADIFFAREA 0.018 ;
		ANTENNAPARTIALMETALAREA 0.025 ;
	END q[25]

	PIN q[26]
		USE SIGNAL ;
		DIRECTION OUTPUT ;
		SHAPE ABUTMENT ;
		PORT
			LAYER	M1 ;
			RECT	0 38.915 0.25 39.015 ;
			LAYER	M2 ;
			RECT	0 38.915 0.25 39.015 ;
			LAYER	M3 ;
			RECT	0 38.915 0.25 39.015 ;
		END

		ANTENNADIFFAREA 0.018 ;
		ANTENNAPARTIALMETALAREA 0.025 ;
	END q[26]

	PIN q[27]
		USE SIGNAL ;
		DIRECTION OUTPUT ;
		SHAPE ABUTMENT ;
		PORT
			LAYER	M1 ;
			RECT	0 39.445 0.25 39.545 ;
			LAYER	M2 ;
			RECT	0 39.445 0.25 39.545 ;
			LAYER	M3 ;
			RECT	0 39.445 0.25 39.545 ;
		END

		ANTENNADIFFAREA 0.018 ;
		ANTENNAPARTIALMETALAREA 0.025 ;
	END q[27]

	PIN q[28]
		USE SIGNAL ;
		DIRECTION OUTPUT ;
		SHAPE ABUTMENT ;
		PORT
			LAYER	M1 ;
			RECT	0 41.755 0.25 41.855 ;
			LAYER	M2 ;
			RECT	0 41.755 0.25 41.855 ;
			LAYER	M3 ;
			RECT	0 41.755 0.25 41.855 ;
		END

		ANTENNADIFFAREA 0.018 ;
		ANTENNAPARTIALMETALAREA 0.025 ;
	END q[28]

	PIN q[29]
		USE SIGNAL ;
		DIRECTION OUTPUT ;
		SHAPE ABUTMENT ;
		PORT
			LAYER	M1 ;
			RECT	0 42.285 0.25 42.385 ;
			LAYER	M2 ;
			RECT	0 42.285 0.25 42.385 ;
			LAYER	M3 ;
			RECT	0 42.285 0.25 42.385 ;
		END

		ANTENNADIFFAREA 0.018 ;
		ANTENNAPARTIALMETALAREA 0.025 ;
	END q[29]

	PIN q[2]
		USE SIGNAL ;
		DIRECTION OUTPUT ;
		SHAPE ABUTMENT ;
		PORT
			LAYER	M1 ;
			RECT	0 4.835 0.25 4.935 ;
			LAYER	M2 ;
			RECT	0 4.835 0.25 4.935 ;
			LAYER	M3 ;
			RECT	0 4.835 0.25 4.935 ;
		END

		ANTENNADIFFAREA 0.018 ;
		ANTENNAPARTIALMETALAREA 0.025 ;
	END q[2]

	PIN q[30]
		USE SIGNAL ;
		DIRECTION OUTPUT ;
		SHAPE ABUTMENT ;
		PORT
			LAYER	M1 ;
			RECT	0 44.595 0.25 44.695 ;
			LAYER	M2 ;
			RECT	0 44.595 0.25 44.695 ;
			LAYER	M3 ;
			RECT	0 44.595 0.25 44.695 ;
		END

		ANTENNADIFFAREA 0.018 ;
		ANTENNAPARTIALMETALAREA 0.025 ;
	END q[30]

	PIN q[31]
		USE SIGNAL ;
		DIRECTION OUTPUT ;
		SHAPE ABUTMENT ;
		PORT
			LAYER	M1 ;
			RECT	0 45.125 0.25 45.225 ;
			LAYER	M2 ;
			RECT	0 45.125 0.25 45.225 ;
			LAYER	M3 ;
			RECT	0 45.125 0.25 45.225 ;
		END

		ANTENNADIFFAREA 0.018 ;
		ANTENNAPARTIALMETALAREA 0.025 ;
	END q[31]

	PIN q[32]
		USE SIGNAL ;
		DIRECTION OUTPUT ;
		SHAPE ABUTMENT ;
		PORT
			LAYER	M1 ;
			RECT	0 69.92 0.25 70.02 ;
			LAYER	M2 ;
			RECT	0 69.92 0.25 70.02 ;
			LAYER	M3 ;
			RECT	0 69.92 0.25 70.02 ;
		END

		ANTENNADIFFAREA 0.018 ;
		ANTENNAPARTIALMETALAREA 0.025 ;
	END q[32]

	PIN q[33]
		USE SIGNAL ;
		DIRECTION OUTPUT ;
		SHAPE ABUTMENT ;
		PORT
			LAYER	M1 ;
			RECT	0 70.45 0.25 70.55 ;
			LAYER	M2 ;
			RECT	0 70.45 0.25 70.55 ;
			LAYER	M3 ;
			RECT	0 70.45 0.25 70.55 ;
		END

		ANTENNADIFFAREA 0.018 ;
		ANTENNAPARTIALMETALAREA 0.025 ;
	END q[33]

	PIN q[34]
		USE SIGNAL ;
		DIRECTION OUTPUT ;
		SHAPE ABUTMENT ;
		PORT
			LAYER	M1 ;
			RECT	0 72.76 0.25 72.86 ;
			LAYER	M2 ;
			RECT	0 72.76 0.25 72.86 ;
			LAYER	M3 ;
			RECT	0 72.76 0.25 72.86 ;
		END

		ANTENNADIFFAREA 0.018 ;
		ANTENNAPARTIALMETALAREA 0.025 ;
	END q[34]

	PIN q[35]
		USE SIGNAL ;
		DIRECTION OUTPUT ;
		SHAPE ABUTMENT ;
		PORT
			LAYER	M1 ;
			RECT	0 73.29 0.25 73.39 ;
			LAYER	M2 ;
			RECT	0 73.29 0.25 73.39 ;
			LAYER	M3 ;
			RECT	0 73.29 0.25 73.39 ;
		END

		ANTENNADIFFAREA 0.018 ;
		ANTENNAPARTIALMETALAREA 0.025 ;
	END q[35]

	PIN q[36]
		USE SIGNAL ;
		DIRECTION OUTPUT ;
		SHAPE ABUTMENT ;
		PORT
			LAYER	M1 ;
			RECT	0 75.6 0.25 75.7 ;
			LAYER	M2 ;
			RECT	0 75.6 0.25 75.7 ;
			LAYER	M3 ;
			RECT	0 75.6 0.25 75.7 ;
		END

		ANTENNADIFFAREA 0.018 ;
		ANTENNAPARTIALMETALAREA 0.025 ;
	END q[36]

	PIN q[37]
		USE SIGNAL ;
		DIRECTION OUTPUT ;
		SHAPE ABUTMENT ;
		PORT
			LAYER	M1 ;
			RECT	0 76.13 0.25 76.23 ;
			LAYER	M2 ;
			RECT	0 76.13 0.25 76.23 ;
			LAYER	M3 ;
			RECT	0 76.13 0.25 76.23 ;
		END

		ANTENNADIFFAREA 0.018 ;
		ANTENNAPARTIALMETALAREA 0.025 ;
	END q[37]

	PIN q[38]
		USE SIGNAL ;
		DIRECTION OUTPUT ;
		SHAPE ABUTMENT ;
		PORT
			LAYER	M1 ;
			RECT	0 78.44 0.25 78.54 ;
			LAYER	M2 ;
			RECT	0 78.44 0.25 78.54 ;
			LAYER	M3 ;
			RECT	0 78.44 0.25 78.54 ;
		END

		ANTENNADIFFAREA 0.018 ;
		ANTENNAPARTIALMETALAREA 0.025 ;
	END q[38]

	PIN q[39]
		USE SIGNAL ;
		DIRECTION OUTPUT ;
		SHAPE ABUTMENT ;
		PORT
			LAYER	M1 ;
			RECT	0 78.97 0.25 79.07 ;
			LAYER	M2 ;
			RECT	0 78.97 0.25 79.07 ;
			LAYER	M3 ;
			RECT	0 78.97 0.25 79.07 ;
		END

		ANTENNADIFFAREA 0.018 ;
		ANTENNAPARTIALMETALAREA 0.025 ;
	END q[39]

	PIN q[3]
		USE SIGNAL ;
		DIRECTION OUTPUT ;
		SHAPE ABUTMENT ;
		PORT
			LAYER	M1 ;
			RECT	0 5.365 0.25 5.465 ;
			LAYER	M2 ;
			RECT	0 5.365 0.25 5.465 ;
			LAYER	M3 ;
			RECT	0 5.365 0.25 5.465 ;
		END

		ANTENNADIFFAREA 0.018 ;
		ANTENNAPARTIALMETALAREA 0.025 ;
	END q[3]

	PIN q[40]
		USE SIGNAL ;
		DIRECTION OUTPUT ;
		SHAPE ABUTMENT ;
		PORT
			LAYER	M1 ;
			RECT	0 81.28 0.25 81.38 ;
			LAYER	M2 ;
			RECT	0 81.28 0.25 81.38 ;
			LAYER	M3 ;
			RECT	0 81.28 0.25 81.38 ;
		END

		ANTENNADIFFAREA 0.018 ;
		ANTENNAPARTIALMETALAREA 0.025 ;
	END q[40]

	PIN q[41]
		USE SIGNAL ;
		DIRECTION OUTPUT ;
		SHAPE ABUTMENT ;
		PORT
			LAYER	M1 ;
			RECT	0 81.81 0.25 81.91 ;
			LAYER	M2 ;
			RECT	0 81.81 0.25 81.91 ;
			LAYER	M3 ;
			RECT	0 81.81 0.25 81.91 ;
		END

		ANTENNADIFFAREA 0.018 ;
		ANTENNAPARTIALMETALAREA 0.025 ;
	END q[41]

	PIN q[42]
		USE SIGNAL ;
		DIRECTION OUTPUT ;
		SHAPE ABUTMENT ;
		PORT
			LAYER	M1 ;
			RECT	0 84.12 0.25 84.22 ;
			LAYER	M2 ;
			RECT	0 84.12 0.25 84.22 ;
			LAYER	M3 ;
			RECT	0 84.12 0.25 84.22 ;
		END

		ANTENNADIFFAREA 0.018 ;
		ANTENNAPARTIALMETALAREA 0.025 ;
	END q[42]

	PIN q[43]
		USE SIGNAL ;
		DIRECTION OUTPUT ;
		SHAPE ABUTMENT ;
		PORT
			LAYER	M1 ;
			RECT	0 84.65 0.25 84.75 ;
			LAYER	M2 ;
			RECT	0 84.65 0.25 84.75 ;
			LAYER	M3 ;
			RECT	0 84.65 0.25 84.75 ;
		END

		ANTENNADIFFAREA 0.018 ;
		ANTENNAPARTIALMETALAREA 0.025 ;
	END q[43]

	PIN q[44]
		USE SIGNAL ;
		DIRECTION OUTPUT ;
		SHAPE ABUTMENT ;
		PORT
			LAYER	M1 ;
			RECT	0 86.96 0.25 87.06 ;
			LAYER	M2 ;
			RECT	0 86.96 0.25 87.06 ;
			LAYER	M3 ;
			RECT	0 86.96 0.25 87.06 ;
		END

		ANTENNADIFFAREA 0.018 ;
		ANTENNAPARTIALMETALAREA 0.025 ;
	END q[44]

	PIN q[45]
		USE SIGNAL ;
		DIRECTION OUTPUT ;
		SHAPE ABUTMENT ;
		PORT
			LAYER	M1 ;
			RECT	0 87.49 0.25 87.59 ;
			LAYER	M2 ;
			RECT	0 87.49 0.25 87.59 ;
			LAYER	M3 ;
			RECT	0 87.49 0.25 87.59 ;
		END

		ANTENNADIFFAREA 0.018 ;
		ANTENNAPARTIALMETALAREA 0.025 ;
	END q[45]

	PIN q[46]
		USE SIGNAL ;
		DIRECTION OUTPUT ;
		SHAPE ABUTMENT ;
		PORT
			LAYER	M1 ;
			RECT	0 89.8 0.25 89.9 ;
			LAYER	M2 ;
			RECT	0 89.8 0.25 89.9 ;
			LAYER	M3 ;
			RECT	0 89.8 0.25 89.9 ;
		END

		ANTENNADIFFAREA 0.018 ;
		ANTENNAPARTIALMETALAREA 0.025 ;
	END q[46]

	PIN q[47]
		USE SIGNAL ;
		DIRECTION OUTPUT ;
		SHAPE ABUTMENT ;
		PORT
			LAYER	M1 ;
			RECT	0 90.33 0.25 90.43 ;
			LAYER	M2 ;
			RECT	0 90.33 0.25 90.43 ;
			LAYER	M3 ;
			RECT	0 90.33 0.25 90.43 ;
		END

		ANTENNADIFFAREA 0.018 ;
		ANTENNAPARTIALMETALAREA 0.025 ;
	END q[47]

	PIN q[48]
		USE SIGNAL ;
		DIRECTION OUTPUT ;
		SHAPE ABUTMENT ;
		PORT
			LAYER	M1 ;
			RECT	0 92.64 0.25 92.74 ;
			LAYER	M2 ;
			RECT	0 92.64 0.25 92.74 ;
			LAYER	M3 ;
			RECT	0 92.64 0.25 92.74 ;
		END

		ANTENNADIFFAREA 0.018 ;
		ANTENNAPARTIALMETALAREA 0.025 ;
	END q[48]

	PIN q[49]
		USE SIGNAL ;
		DIRECTION OUTPUT ;
		SHAPE ABUTMENT ;
		PORT
			LAYER	M1 ;
			RECT	0 93.17 0.25 93.27 ;
			LAYER	M2 ;
			RECT	0 93.17 0.25 93.27 ;
			LAYER	M3 ;
			RECT	0 93.17 0.25 93.27 ;
		END

		ANTENNADIFFAREA 0.018 ;
		ANTENNAPARTIALMETALAREA 0.025 ;
	END q[49]

	PIN q[4]
		USE SIGNAL ;
		DIRECTION OUTPUT ;
		SHAPE ABUTMENT ;
		PORT
			LAYER	M1 ;
			RECT	0 7.675 0.25 7.775 ;
			LAYER	M2 ;
			RECT	0 7.675 0.25 7.775 ;
			LAYER	M3 ;
			RECT	0 7.675 0.25 7.775 ;
		END

		ANTENNADIFFAREA 0.018 ;
		ANTENNAPARTIALMETALAREA 0.025 ;
	END q[4]

	PIN q[50]
		USE SIGNAL ;
		DIRECTION OUTPUT ;
		SHAPE ABUTMENT ;
		PORT
			LAYER	M1 ;
			RECT	0 95.48 0.25 95.58 ;
			LAYER	M2 ;
			RECT	0 95.48 0.25 95.58 ;
			LAYER	M3 ;
			RECT	0 95.48 0.25 95.58 ;
		END

		ANTENNADIFFAREA 0.018 ;
		ANTENNAPARTIALMETALAREA 0.025 ;
	END q[50]

	PIN q[51]
		USE SIGNAL ;
		DIRECTION OUTPUT ;
		SHAPE ABUTMENT ;
		PORT
			LAYER	M1 ;
			RECT	0 96.01 0.25 96.11 ;
			LAYER	M2 ;
			RECT	0 96.01 0.25 96.11 ;
			LAYER	M3 ;
			RECT	0 96.01 0.25 96.11 ;
		END

		ANTENNADIFFAREA 0.018 ;
		ANTENNAPARTIALMETALAREA 0.025 ;
	END q[51]

	PIN q[52]
		USE SIGNAL ;
		DIRECTION OUTPUT ;
		SHAPE ABUTMENT ;
		PORT
			LAYER	M1 ;
			RECT	0 98.32 0.25 98.42 ;
			LAYER	M2 ;
			RECT	0 98.32 0.25 98.42 ;
			LAYER	M3 ;
			RECT	0 98.32 0.25 98.42 ;
		END

		ANTENNADIFFAREA 0.018 ;
		ANTENNAPARTIALMETALAREA 0.025 ;
	END q[52]

	PIN q[53]
		USE SIGNAL ;
		DIRECTION OUTPUT ;
		SHAPE ABUTMENT ;
		PORT
			LAYER	M1 ;
			RECT	0 98.85 0.25 98.95 ;
			LAYER	M2 ;
			RECT	0 98.85 0.25 98.95 ;
			LAYER	M3 ;
			RECT	0 98.85 0.25 98.95 ;
		END

		ANTENNADIFFAREA 0.018 ;
		ANTENNAPARTIALMETALAREA 0.025 ;
	END q[53]

	PIN q[54]
		USE SIGNAL ;
		DIRECTION OUTPUT ;
		SHAPE ABUTMENT ;
		PORT
			LAYER	M1 ;
			RECT	0 101.16 0.25 101.26 ;
			LAYER	M2 ;
			RECT	0 101.16 0.25 101.26 ;
			LAYER	M3 ;
			RECT	0 101.16 0.25 101.26 ;
		END

		ANTENNADIFFAREA 0.018 ;
		ANTENNAPARTIALMETALAREA 0.025 ;
	END q[54]

	PIN q[55]
		USE SIGNAL ;
		DIRECTION OUTPUT ;
		SHAPE ABUTMENT ;
		PORT
			LAYER	M1 ;
			RECT	0 101.69 0.25 101.79 ;
			LAYER	M2 ;
			RECT	0 101.69 0.25 101.79 ;
			LAYER	M3 ;
			RECT	0 101.69 0.25 101.79 ;
		END

		ANTENNADIFFAREA 0.018 ;
		ANTENNAPARTIALMETALAREA 0.025 ;
	END q[55]

	PIN q[56]
		USE SIGNAL ;
		DIRECTION OUTPUT ;
		SHAPE ABUTMENT ;
		PORT
			LAYER	M1 ;
			RECT	0 104 0.25 104.1 ;
			LAYER	M2 ;
			RECT	0 104 0.25 104.1 ;
			LAYER	M3 ;
			RECT	0 104 0.25 104.1 ;
		END

		ANTENNADIFFAREA 0.018 ;
		ANTENNAPARTIALMETALAREA 0.025 ;
	END q[56]

	PIN q[57]
		USE SIGNAL ;
		DIRECTION OUTPUT ;
		SHAPE ABUTMENT ;
		PORT
			LAYER	M1 ;
			RECT	0 104.53 0.25 104.63 ;
			LAYER	M2 ;
			RECT	0 104.53 0.25 104.63 ;
			LAYER	M3 ;
			RECT	0 104.53 0.25 104.63 ;
		END

		ANTENNADIFFAREA 0.018 ;
		ANTENNAPARTIALMETALAREA 0.025 ;
	END q[57]

	PIN q[58]
		USE SIGNAL ;
		DIRECTION OUTPUT ;
		SHAPE ABUTMENT ;
		PORT
			LAYER	M1 ;
			RECT	0 106.84 0.25 106.94 ;
			LAYER	M2 ;
			RECT	0 106.84 0.25 106.94 ;
			LAYER	M3 ;
			RECT	0 106.84 0.25 106.94 ;
		END

		ANTENNADIFFAREA 0.018 ;
		ANTENNAPARTIALMETALAREA 0.025 ;
	END q[58]

	PIN q[59]
		USE SIGNAL ;
		DIRECTION OUTPUT ;
		SHAPE ABUTMENT ;
		PORT
			LAYER	M1 ;
			RECT	0 107.37 0.25 107.47 ;
			LAYER	M2 ;
			RECT	0 107.37 0.25 107.47 ;
			LAYER	M3 ;
			RECT	0 107.37 0.25 107.47 ;
		END

		ANTENNADIFFAREA 0.018 ;
		ANTENNAPARTIALMETALAREA 0.025 ;
	END q[59]

	PIN q[5]
		USE SIGNAL ;
		DIRECTION OUTPUT ;
		SHAPE ABUTMENT ;
		PORT
			LAYER	M1 ;
			RECT	0 8.205 0.25 8.305 ;
			LAYER	M2 ;
			RECT	0 8.205 0.25 8.305 ;
			LAYER	M3 ;
			RECT	0 8.205 0.25 8.305 ;
		END

		ANTENNADIFFAREA 0.018 ;
		ANTENNAPARTIALMETALAREA 0.025 ;
	END q[5]

	PIN q[60]
		USE SIGNAL ;
		DIRECTION OUTPUT ;
		SHAPE ABUTMENT ;
		PORT
			LAYER	M1 ;
			RECT	0 109.68 0.25 109.78 ;
			LAYER	M2 ;
			RECT	0 109.68 0.25 109.78 ;
			LAYER	M3 ;
			RECT	0 109.68 0.25 109.78 ;
		END

		ANTENNADIFFAREA 0.018 ;
		ANTENNAPARTIALMETALAREA 0.025 ;
	END q[60]

	PIN q[61]
		USE SIGNAL ;
		DIRECTION OUTPUT ;
		SHAPE ABUTMENT ;
		PORT
			LAYER	M1 ;
			RECT	0 110.21 0.25 110.31 ;
			LAYER	M2 ;
			RECT	0 110.21 0.25 110.31 ;
			LAYER	M3 ;
			RECT	0 110.21 0.25 110.31 ;
		END

		ANTENNADIFFAREA 0.018 ;
		ANTENNAPARTIALMETALAREA 0.025 ;
	END q[61]

	PIN q[62]
		USE SIGNAL ;
		DIRECTION OUTPUT ;
		SHAPE ABUTMENT ;
		PORT
			LAYER	M1 ;
			RECT	0 112.52 0.25 112.62 ;
			LAYER	M2 ;
			RECT	0 112.52 0.25 112.62 ;
			LAYER	M3 ;
			RECT	0 112.52 0.25 112.62 ;
		END

		ANTENNADIFFAREA 0.018 ;
		ANTENNAPARTIALMETALAREA 0.025 ;
	END q[62]

	PIN q[63]
		USE SIGNAL ;
		DIRECTION OUTPUT ;
		SHAPE ABUTMENT ;
		PORT
			LAYER	M1 ;
			RECT	0 113.05 0.25 113.15 ;
			LAYER	M2 ;
			RECT	0 113.05 0.25 113.15 ;
			LAYER	M3 ;
			RECT	0 113.05 0.25 113.15 ;
		END

		ANTENNADIFFAREA 0.018 ;
		ANTENNAPARTIALMETALAREA 0.025 ;
	END q[63]

	PIN q[6]
		USE SIGNAL ;
		DIRECTION OUTPUT ;
		SHAPE ABUTMENT ;
		PORT
			LAYER	M1 ;
			RECT	0 10.515 0.25 10.615 ;
			LAYER	M2 ;
			RECT	0 10.515 0.25 10.615 ;
			LAYER	M3 ;
			RECT	0 10.515 0.25 10.615 ;
		END

		ANTENNADIFFAREA 0.018 ;
		ANTENNAPARTIALMETALAREA 0.025 ;
	END q[6]

	PIN q[7]
		USE SIGNAL ;
		DIRECTION OUTPUT ;
		SHAPE ABUTMENT ;
		PORT
			LAYER	M1 ;
			RECT	0 11.045 0.25 11.145 ;
			LAYER	M2 ;
			RECT	0 11.045 0.25 11.145 ;
			LAYER	M3 ;
			RECT	0 11.045 0.25 11.145 ;
		END

		ANTENNADIFFAREA 0.018 ;
		ANTENNAPARTIALMETALAREA 0.025 ;
	END q[7]

	PIN q[8]
		USE SIGNAL ;
		DIRECTION OUTPUT ;
		SHAPE ABUTMENT ;
		PORT
			LAYER	M1 ;
			RECT	0 13.355 0.25 13.455 ;
			LAYER	M2 ;
			RECT	0 13.355 0.25 13.455 ;
			LAYER	M3 ;
			RECT	0 13.355 0.25 13.455 ;
		END

		ANTENNADIFFAREA 0.018 ;
		ANTENNAPARTIALMETALAREA 0.025 ;
	END q[8]

	PIN q[9]
		USE SIGNAL ;
		DIRECTION OUTPUT ;
		SHAPE ABUTMENT ;
		PORT
			LAYER	M1 ;
			RECT	0 13.885 0.25 13.985 ;
			LAYER	M2 ;
			RECT	0 13.885 0.25 13.985 ;
			LAYER	M3 ;
			RECT	0 13.885 0.25 13.985 ;
		END

		ANTENNADIFFAREA 0.018 ;
		ANTENNAPARTIALMETALAREA 0.025 ;
	END q[9]

	PIN ret1n
		USE SIGNAL ;
		DIRECTION INPUT ;
		SHAPE ABUTMENT ;
		PORT
			LAYER	M1 ;
			RECT	0 48.625 0.25 48.725 ;
			LAYER	M2 ;
			RECT	0 48.625 0.25 48.725 ;
			LAYER	M3 ;
			RECT	0 48.625 0.25 48.725 ;
		END

		ANTENNAGATEAREA 0.014 ;
		ANTENNADIFFAREA 0.018 ;
		ANTENNAPARTIALMETALAREA 0.025 ;
	END ret1n

	PIN wen[0]
		USE SIGNAL ;
		DIRECTION INPUT ;
		SHAPE ABUTMENT ;
		PORT
			LAYER	M1 ;
			RECT	0 1.165 0.25 1.265 ;
			LAYER	M2 ;
			RECT	0 1.165 0.25 1.265 ;
			LAYER	M3 ;
			RECT	0 1.165 0.25 1.265 ;
		END

		ANTENNAGATEAREA 0.014 ;
		ANTENNADIFFAREA 0.018 ;
		ANTENNAPARTIALMETALAREA 0.025 ;
	END wen[0]

	PIN wen[10]
		USE SIGNAL ;
		DIRECTION INPUT ;
		SHAPE ABUTMENT ;
		PORT
			LAYER	M1 ;
			RECT	0 15.365 0.25 15.465 ;
			LAYER	M2 ;
			RECT	0 15.365 0.25 15.465 ;
			LAYER	M3 ;
			RECT	0 15.365 0.25 15.465 ;
		END

		ANTENNAGATEAREA 0.014 ;
		ANTENNADIFFAREA 0.018 ;
		ANTENNAPARTIALMETALAREA 0.025 ;
	END wen[10]

	PIN wen[11]
		USE SIGNAL ;
		DIRECTION INPUT ;
		SHAPE ABUTMENT ;
		PORT
			LAYER	M1 ;
			RECT	0 17.555 0.25 17.655 ;
			LAYER	M2 ;
			RECT	0 17.555 0.25 17.655 ;
			LAYER	M3 ;
			RECT	0 17.555 0.25 17.655 ;
		END

		ANTENNAGATEAREA 0.014 ;
		ANTENNADIFFAREA 0.018 ;
		ANTENNAPARTIALMETALAREA 0.025 ;
	END wen[11]

	PIN wen[12]
		USE SIGNAL ;
		DIRECTION INPUT ;
		SHAPE ABUTMENT ;
		PORT
			LAYER	M1 ;
			RECT	0 18.205 0.25 18.305 ;
			LAYER	M2 ;
			RECT	0 18.205 0.25 18.305 ;
			LAYER	M3 ;
			RECT	0 18.205 0.25 18.305 ;
		END

		ANTENNAGATEAREA 0.014 ;
		ANTENNADIFFAREA 0.018 ;
		ANTENNAPARTIALMETALAREA 0.025 ;
	END wen[12]

	PIN wen[13]
		USE SIGNAL ;
		DIRECTION INPUT ;
		SHAPE ABUTMENT ;
		PORT
			LAYER	M1 ;
			RECT	0 20.395 0.25 20.495 ;
			LAYER	M2 ;
			RECT	0 20.395 0.25 20.495 ;
			LAYER	M3 ;
			RECT	0 20.395 0.25 20.495 ;
		END

		ANTENNAGATEAREA 0.014 ;
		ANTENNADIFFAREA 0.018 ;
		ANTENNAPARTIALMETALAREA 0.025 ;
	END wen[13]

	PIN wen[14]
		USE SIGNAL ;
		DIRECTION INPUT ;
		SHAPE ABUTMENT ;
		PORT
			LAYER	M1 ;
			RECT	0 21.045 0.25 21.145 ;
			LAYER	M2 ;
			RECT	0 21.045 0.25 21.145 ;
			LAYER	M3 ;
			RECT	0 21.045 0.25 21.145 ;
		END

		ANTENNAGATEAREA 0.014 ;
		ANTENNADIFFAREA 0.018 ;
		ANTENNAPARTIALMETALAREA 0.025 ;
	END wen[14]

	PIN wen[15]
		USE SIGNAL ;
		DIRECTION INPUT ;
		SHAPE ABUTMENT ;
		PORT
			LAYER	M1 ;
			RECT	0 23.235 0.25 23.335 ;
			LAYER	M2 ;
			RECT	0 23.235 0.25 23.335 ;
			LAYER	M3 ;
			RECT	0 23.235 0.25 23.335 ;
		END

		ANTENNAGATEAREA 0.014 ;
		ANTENNADIFFAREA 0.018 ;
		ANTENNAPARTIALMETALAREA 0.025 ;
	END wen[15]

	PIN wen[16]
		USE SIGNAL ;
		DIRECTION INPUT ;
		SHAPE ABUTMENT ;
		PORT
			LAYER	M1 ;
			RECT	0 23.885 0.25 23.985 ;
			LAYER	M2 ;
			RECT	0 23.885 0.25 23.985 ;
			LAYER	M3 ;
			RECT	0 23.885 0.25 23.985 ;
		END

		ANTENNAGATEAREA 0.014 ;
		ANTENNADIFFAREA 0.018 ;
		ANTENNAPARTIALMETALAREA 0.025 ;
	END wen[16]

	PIN wen[17]
		USE SIGNAL ;
		DIRECTION INPUT ;
		SHAPE ABUTMENT ;
		PORT
			LAYER	M1 ;
			RECT	0 26.075 0.25 26.175 ;
			LAYER	M2 ;
			RECT	0 26.075 0.25 26.175 ;
			LAYER	M3 ;
			RECT	0 26.075 0.25 26.175 ;
		END

		ANTENNAGATEAREA 0.014 ;
		ANTENNADIFFAREA 0.018 ;
		ANTENNAPARTIALMETALAREA 0.025 ;
	END wen[17]

	PIN wen[18]
		USE SIGNAL ;
		DIRECTION INPUT ;
		SHAPE ABUTMENT ;
		PORT
			LAYER	M1 ;
			RECT	0 26.725 0.25 26.825 ;
			LAYER	M2 ;
			RECT	0 26.725 0.25 26.825 ;
			LAYER	M3 ;
			RECT	0 26.725 0.25 26.825 ;
		END

		ANTENNAGATEAREA 0.014 ;
		ANTENNADIFFAREA 0.018 ;
		ANTENNAPARTIALMETALAREA 0.025 ;
	END wen[18]

	PIN wen[19]
		USE SIGNAL ;
		DIRECTION INPUT ;
		SHAPE ABUTMENT ;
		PORT
			LAYER	M1 ;
			RECT	0 28.915 0.25 29.015 ;
			LAYER	M2 ;
			RECT	0 28.915 0.25 29.015 ;
			LAYER	M3 ;
			RECT	0 28.915 0.25 29.015 ;
		END

		ANTENNAGATEAREA 0.014 ;
		ANTENNADIFFAREA 0.018 ;
		ANTENNAPARTIALMETALAREA 0.025 ;
	END wen[19]

	PIN wen[1]
		USE SIGNAL ;
		DIRECTION INPUT ;
		SHAPE ABUTMENT ;
		PORT
			LAYER	M1 ;
			RECT	0 3.355 0.25 3.455 ;
			LAYER	M2 ;
			RECT	0 3.355 0.25 3.455 ;
			LAYER	M3 ;
			RECT	0 3.355 0.25 3.455 ;
		END

		ANTENNAGATEAREA 0.014 ;
		ANTENNADIFFAREA 0.018 ;
		ANTENNAPARTIALMETALAREA 0.025 ;
	END wen[1]

	PIN wen[20]
		USE SIGNAL ;
		DIRECTION INPUT ;
		SHAPE ABUTMENT ;
		PORT
			LAYER	M1 ;
			RECT	0 29.565 0.25 29.665 ;
			LAYER	M2 ;
			RECT	0 29.565 0.25 29.665 ;
			LAYER	M3 ;
			RECT	0 29.565 0.25 29.665 ;
		END

		ANTENNAGATEAREA 0.014 ;
		ANTENNADIFFAREA 0.018 ;
		ANTENNAPARTIALMETALAREA 0.025 ;
	END wen[20]

	PIN wen[21]
		USE SIGNAL ;
		DIRECTION INPUT ;
		SHAPE ABUTMENT ;
		PORT
			LAYER	M1 ;
			RECT	0 31.755 0.25 31.855 ;
			LAYER	M2 ;
			RECT	0 31.755 0.25 31.855 ;
			LAYER	M3 ;
			RECT	0 31.755 0.25 31.855 ;
		END

		ANTENNAGATEAREA 0.014 ;
		ANTENNADIFFAREA 0.018 ;
		ANTENNAPARTIALMETALAREA 0.025 ;
	END wen[21]

	PIN wen[22]
		USE SIGNAL ;
		DIRECTION INPUT ;
		SHAPE ABUTMENT ;
		PORT
			LAYER	M1 ;
			RECT	0 32.405 0.25 32.505 ;
			LAYER	M2 ;
			RECT	0 32.405 0.25 32.505 ;
			LAYER	M3 ;
			RECT	0 32.405 0.25 32.505 ;
		END

		ANTENNAGATEAREA 0.014 ;
		ANTENNADIFFAREA 0.018 ;
		ANTENNAPARTIALMETALAREA 0.025 ;
	END wen[22]

	PIN wen[23]
		USE SIGNAL ;
		DIRECTION INPUT ;
		SHAPE ABUTMENT ;
		PORT
			LAYER	M1 ;
			RECT	0 34.595 0.25 34.695 ;
			LAYER	M2 ;
			RECT	0 34.595 0.25 34.695 ;
			LAYER	M3 ;
			RECT	0 34.595 0.25 34.695 ;
		END

		ANTENNAGATEAREA 0.014 ;
		ANTENNADIFFAREA 0.018 ;
		ANTENNAPARTIALMETALAREA 0.025 ;
	END wen[23]

	PIN wen[24]
		USE SIGNAL ;
		DIRECTION INPUT ;
		SHAPE ABUTMENT ;
		PORT
			LAYER	M1 ;
			RECT	0 35.245 0.25 35.345 ;
			LAYER	M2 ;
			RECT	0 35.245 0.25 35.345 ;
			LAYER	M3 ;
			RECT	0 35.245 0.25 35.345 ;
		END

		ANTENNAGATEAREA 0.014 ;
		ANTENNADIFFAREA 0.018 ;
		ANTENNAPARTIALMETALAREA 0.025 ;
	END wen[24]

	PIN wen[25]
		USE SIGNAL ;
		DIRECTION INPUT ;
		SHAPE ABUTMENT ;
		PORT
			LAYER	M1 ;
			RECT	0 37.435 0.25 37.535 ;
			LAYER	M2 ;
			RECT	0 37.435 0.25 37.535 ;
			LAYER	M3 ;
			RECT	0 37.435 0.25 37.535 ;
		END

		ANTENNAGATEAREA 0.014 ;
		ANTENNADIFFAREA 0.018 ;
		ANTENNAPARTIALMETALAREA 0.025 ;
	END wen[25]

	PIN wen[26]
		USE SIGNAL ;
		DIRECTION INPUT ;
		SHAPE ABUTMENT ;
		PORT
			LAYER	M1 ;
			RECT	0 38.085 0.25 38.185 ;
			LAYER	M2 ;
			RECT	0 38.085 0.25 38.185 ;
			LAYER	M3 ;
			RECT	0 38.085 0.25 38.185 ;
		END

		ANTENNAGATEAREA 0.014 ;
		ANTENNADIFFAREA 0.018 ;
		ANTENNAPARTIALMETALAREA 0.025 ;
	END wen[26]

	PIN wen[27]
		USE SIGNAL ;
		DIRECTION INPUT ;
		SHAPE ABUTMENT ;
		PORT
			LAYER	M1 ;
			RECT	0 40.275 0.25 40.375 ;
			LAYER	M2 ;
			RECT	0 40.275 0.25 40.375 ;
			LAYER	M3 ;
			RECT	0 40.275 0.25 40.375 ;
		END

		ANTENNAGATEAREA 0.014 ;
		ANTENNADIFFAREA 0.018 ;
		ANTENNAPARTIALMETALAREA 0.025 ;
	END wen[27]

	PIN wen[28]
		USE SIGNAL ;
		DIRECTION INPUT ;
		SHAPE ABUTMENT ;
		PORT
			LAYER	M1 ;
			RECT	0 40.925 0.25 41.025 ;
			LAYER	M2 ;
			RECT	0 40.925 0.25 41.025 ;
			LAYER	M3 ;
			RECT	0 40.925 0.25 41.025 ;
		END

		ANTENNAGATEAREA 0.014 ;
		ANTENNADIFFAREA 0.018 ;
		ANTENNAPARTIALMETALAREA 0.025 ;
	END wen[28]

	PIN wen[29]
		USE SIGNAL ;
		DIRECTION INPUT ;
		SHAPE ABUTMENT ;
		PORT
			LAYER	M1 ;
			RECT	0 43.115 0.25 43.215 ;
			LAYER	M2 ;
			RECT	0 43.115 0.25 43.215 ;
			LAYER	M3 ;
			RECT	0 43.115 0.25 43.215 ;
		END

		ANTENNAGATEAREA 0.014 ;
		ANTENNADIFFAREA 0.018 ;
		ANTENNAPARTIALMETALAREA 0.025 ;
	END wen[29]

	PIN wen[2]
		USE SIGNAL ;
		DIRECTION INPUT ;
		SHAPE ABUTMENT ;
		PORT
			LAYER	M1 ;
			RECT	0 4.005 0.25 4.105 ;
			LAYER	M2 ;
			RECT	0 4.005 0.25 4.105 ;
			LAYER	M3 ;
			RECT	0 4.005 0.25 4.105 ;
		END

		ANTENNAGATEAREA 0.014 ;
		ANTENNADIFFAREA 0.018 ;
		ANTENNAPARTIALMETALAREA 0.025 ;
	END wen[2]

	PIN wen[30]
		USE SIGNAL ;
		DIRECTION INPUT ;
		SHAPE ABUTMENT ;
		PORT
			LAYER	M1 ;
			RECT	0 43.765 0.25 43.865 ;
			LAYER	M2 ;
			RECT	0 43.765 0.25 43.865 ;
			LAYER	M3 ;
			RECT	0 43.765 0.25 43.865 ;
		END

		ANTENNAGATEAREA 0.014 ;
		ANTENNADIFFAREA 0.018 ;
		ANTENNAPARTIALMETALAREA 0.025 ;
	END wen[30]

	PIN wen[31]
		USE SIGNAL ;
		DIRECTION INPUT ;
		SHAPE ABUTMENT ;
		PORT
			LAYER	M1 ;
			RECT	0 45.955 0.25 46.055 ;
			LAYER	M2 ;
			RECT	0 45.955 0.25 46.055 ;
			LAYER	M3 ;
			RECT	0 45.955 0.25 46.055 ;
		END

		ANTENNAGATEAREA 0.014 ;
		ANTENNADIFFAREA 0.018 ;
		ANTENNAPARTIALMETALAREA 0.025 ;
	END wen[31]

	PIN wen[32]
		USE SIGNAL ;
		DIRECTION INPUT ;
		SHAPE ABUTMENT ;
		PORT
			LAYER	M1 ;
			RECT	0 69.09 0.25 69.19 ;
			LAYER	M2 ;
			RECT	0 69.09 0.25 69.19 ;
			LAYER	M3 ;
			RECT	0 69.09 0.25 69.19 ;
		END

		ANTENNAGATEAREA 0.014 ;
		ANTENNADIFFAREA 0.018 ;
		ANTENNAPARTIALMETALAREA 0.025 ;
	END wen[32]

	PIN wen[33]
		USE SIGNAL ;
		DIRECTION INPUT ;
		SHAPE ABUTMENT ;
		PORT
			LAYER	M1 ;
			RECT	0 71.28 0.25 71.38 ;
			LAYER	M2 ;
			RECT	0 71.28 0.25 71.38 ;
			LAYER	M3 ;
			RECT	0 71.28 0.25 71.38 ;
		END

		ANTENNAGATEAREA 0.014 ;
		ANTENNADIFFAREA 0.018 ;
		ANTENNAPARTIALMETALAREA 0.025 ;
	END wen[33]

	PIN wen[34]
		USE SIGNAL ;
		DIRECTION INPUT ;
		SHAPE ABUTMENT ;
		PORT
			LAYER	M1 ;
			RECT	0 71.93 0.25 72.03 ;
			LAYER	M2 ;
			RECT	0 71.93 0.25 72.03 ;
			LAYER	M3 ;
			RECT	0 71.93 0.25 72.03 ;
		END

		ANTENNAGATEAREA 0.014 ;
		ANTENNADIFFAREA 0.018 ;
		ANTENNAPARTIALMETALAREA 0.025 ;
	END wen[34]

	PIN wen[35]
		USE SIGNAL ;
		DIRECTION INPUT ;
		SHAPE ABUTMENT ;
		PORT
			LAYER	M1 ;
			RECT	0 74.12 0.25 74.22 ;
			LAYER	M2 ;
			RECT	0 74.12 0.25 74.22 ;
			LAYER	M3 ;
			RECT	0 74.12 0.25 74.22 ;
		END

		ANTENNAGATEAREA 0.014 ;
		ANTENNADIFFAREA 0.018 ;
		ANTENNAPARTIALMETALAREA 0.025 ;
	END wen[35]

	PIN wen[36]
		USE SIGNAL ;
		DIRECTION INPUT ;
		SHAPE ABUTMENT ;
		PORT
			LAYER	M1 ;
			RECT	0 74.77 0.25 74.87 ;
			LAYER	M2 ;
			RECT	0 74.77 0.25 74.87 ;
			LAYER	M3 ;
			RECT	0 74.77 0.25 74.87 ;
		END

		ANTENNAGATEAREA 0.014 ;
		ANTENNADIFFAREA 0.018 ;
		ANTENNAPARTIALMETALAREA 0.025 ;
	END wen[36]

	PIN wen[37]
		USE SIGNAL ;
		DIRECTION INPUT ;
		SHAPE ABUTMENT ;
		PORT
			LAYER	M1 ;
			RECT	0 76.96 0.25 77.06 ;
			LAYER	M2 ;
			RECT	0 76.96 0.25 77.06 ;
			LAYER	M3 ;
			RECT	0 76.96 0.25 77.06 ;
		END

		ANTENNAGATEAREA 0.014 ;
		ANTENNADIFFAREA 0.018 ;
		ANTENNAPARTIALMETALAREA 0.025 ;
	END wen[37]

	PIN wen[38]
		USE SIGNAL ;
		DIRECTION INPUT ;
		SHAPE ABUTMENT ;
		PORT
			LAYER	M1 ;
			RECT	0 77.61 0.25 77.71 ;
			LAYER	M2 ;
			RECT	0 77.61 0.25 77.71 ;
			LAYER	M3 ;
			RECT	0 77.61 0.25 77.71 ;
		END

		ANTENNAGATEAREA 0.014 ;
		ANTENNADIFFAREA 0.018 ;
		ANTENNAPARTIALMETALAREA 0.025 ;
	END wen[38]

	PIN wen[39]
		USE SIGNAL ;
		DIRECTION INPUT ;
		SHAPE ABUTMENT ;
		PORT
			LAYER	M1 ;
			RECT	0 79.8 0.25 79.9 ;
			LAYER	M2 ;
			RECT	0 79.8 0.25 79.9 ;
			LAYER	M3 ;
			RECT	0 79.8 0.25 79.9 ;
		END

		ANTENNAGATEAREA 0.014 ;
		ANTENNADIFFAREA 0.018 ;
		ANTENNAPARTIALMETALAREA 0.025 ;
	END wen[39]

	PIN wen[3]
		USE SIGNAL ;
		DIRECTION INPUT ;
		SHAPE ABUTMENT ;
		PORT
			LAYER	M1 ;
			RECT	0 6.195 0.25 6.295 ;
			LAYER	M2 ;
			RECT	0 6.195 0.25 6.295 ;
			LAYER	M3 ;
			RECT	0 6.195 0.25 6.295 ;
		END

		ANTENNAGATEAREA 0.014 ;
		ANTENNADIFFAREA 0.018 ;
		ANTENNAPARTIALMETALAREA 0.025 ;
	END wen[3]

	PIN wen[40]
		USE SIGNAL ;
		DIRECTION INPUT ;
		SHAPE ABUTMENT ;
		PORT
			LAYER	M1 ;
			RECT	0 80.45 0.25 80.55 ;
			LAYER	M2 ;
			RECT	0 80.45 0.25 80.55 ;
			LAYER	M3 ;
			RECT	0 80.45 0.25 80.55 ;
		END

		ANTENNAGATEAREA 0.014 ;
		ANTENNADIFFAREA 0.018 ;
		ANTENNAPARTIALMETALAREA 0.025 ;
	END wen[40]

	PIN wen[41]
		USE SIGNAL ;
		DIRECTION INPUT ;
		SHAPE ABUTMENT ;
		PORT
			LAYER	M1 ;
			RECT	0 82.64 0.25 82.74 ;
			LAYER	M2 ;
			RECT	0 82.64 0.25 82.74 ;
			LAYER	M3 ;
			RECT	0 82.64 0.25 82.74 ;
		END

		ANTENNAGATEAREA 0.014 ;
		ANTENNADIFFAREA 0.018 ;
		ANTENNAPARTIALMETALAREA 0.025 ;
	END wen[41]

	PIN wen[42]
		USE SIGNAL ;
		DIRECTION INPUT ;
		SHAPE ABUTMENT ;
		PORT
			LAYER	M1 ;
			RECT	0 83.29 0.25 83.39 ;
			LAYER	M2 ;
			RECT	0 83.29 0.25 83.39 ;
			LAYER	M3 ;
			RECT	0 83.29 0.25 83.39 ;
		END

		ANTENNAGATEAREA 0.014 ;
		ANTENNADIFFAREA 0.018 ;
		ANTENNAPARTIALMETALAREA 0.025 ;
	END wen[42]

	PIN wen[43]
		USE SIGNAL ;
		DIRECTION INPUT ;
		SHAPE ABUTMENT ;
		PORT
			LAYER	M1 ;
			RECT	0 85.48 0.25 85.58 ;
			LAYER	M2 ;
			RECT	0 85.48 0.25 85.58 ;
			LAYER	M3 ;
			RECT	0 85.48 0.25 85.58 ;
		END

		ANTENNAGATEAREA 0.014 ;
		ANTENNADIFFAREA 0.018 ;
		ANTENNAPARTIALMETALAREA 0.025 ;
	END wen[43]

	PIN wen[44]
		USE SIGNAL ;
		DIRECTION INPUT ;
		SHAPE ABUTMENT ;
		PORT
			LAYER	M1 ;
			RECT	0 86.13 0.25 86.23 ;
			LAYER	M2 ;
			RECT	0 86.13 0.25 86.23 ;
			LAYER	M3 ;
			RECT	0 86.13 0.25 86.23 ;
		END

		ANTENNAGATEAREA 0.014 ;
		ANTENNADIFFAREA 0.018 ;
		ANTENNAPARTIALMETALAREA 0.025 ;
	END wen[44]

	PIN wen[45]
		USE SIGNAL ;
		DIRECTION INPUT ;
		SHAPE ABUTMENT ;
		PORT
			LAYER	M1 ;
			RECT	0 88.32 0.25 88.42 ;
			LAYER	M2 ;
			RECT	0 88.32 0.25 88.42 ;
			LAYER	M3 ;
			RECT	0 88.32 0.25 88.42 ;
		END

		ANTENNAGATEAREA 0.014 ;
		ANTENNADIFFAREA 0.018 ;
		ANTENNAPARTIALMETALAREA 0.025 ;
	END wen[45]

	PIN wen[46]
		USE SIGNAL ;
		DIRECTION INPUT ;
		SHAPE ABUTMENT ;
		PORT
			LAYER	M1 ;
			RECT	0 88.97 0.25 89.07 ;
			LAYER	M2 ;
			RECT	0 88.97 0.25 89.07 ;
			LAYER	M3 ;
			RECT	0 88.97 0.25 89.07 ;
		END

		ANTENNAGATEAREA 0.014 ;
		ANTENNADIFFAREA 0.018 ;
		ANTENNAPARTIALMETALAREA 0.025 ;
	END wen[46]

	PIN wen[47]
		USE SIGNAL ;
		DIRECTION INPUT ;
		SHAPE ABUTMENT ;
		PORT
			LAYER	M1 ;
			RECT	0 91.16 0.25 91.26 ;
			LAYER	M2 ;
			RECT	0 91.16 0.25 91.26 ;
			LAYER	M3 ;
			RECT	0 91.16 0.25 91.26 ;
		END

		ANTENNAGATEAREA 0.014 ;
		ANTENNADIFFAREA 0.018 ;
		ANTENNAPARTIALMETALAREA 0.025 ;
	END wen[47]

	PIN wen[48]
		USE SIGNAL ;
		DIRECTION INPUT ;
		SHAPE ABUTMENT ;
		PORT
			LAYER	M1 ;
			RECT	0 91.81 0.25 91.91 ;
			LAYER	M2 ;
			RECT	0 91.81 0.25 91.91 ;
			LAYER	M3 ;
			RECT	0 91.81 0.25 91.91 ;
		END

		ANTENNAGATEAREA 0.014 ;
		ANTENNADIFFAREA 0.018 ;
		ANTENNAPARTIALMETALAREA 0.025 ;
	END wen[48]

	PIN wen[49]
		USE SIGNAL ;
		DIRECTION INPUT ;
		SHAPE ABUTMENT ;
		PORT
			LAYER	M1 ;
			RECT	0 94 0.25 94.1 ;
			LAYER	M2 ;
			RECT	0 94 0.25 94.1 ;
			LAYER	M3 ;
			RECT	0 94 0.25 94.1 ;
		END

		ANTENNAGATEAREA 0.014 ;
		ANTENNADIFFAREA 0.018 ;
		ANTENNAPARTIALMETALAREA 0.025 ;
	END wen[49]

	PIN wen[4]
		USE SIGNAL ;
		DIRECTION INPUT ;
		SHAPE ABUTMENT ;
		PORT
			LAYER	M1 ;
			RECT	0 6.845 0.25 6.945 ;
			LAYER	M2 ;
			RECT	0 6.845 0.25 6.945 ;
			LAYER	M3 ;
			RECT	0 6.845 0.25 6.945 ;
		END

		ANTENNAGATEAREA 0.014 ;
		ANTENNADIFFAREA 0.018 ;
		ANTENNAPARTIALMETALAREA 0.025 ;
	END wen[4]

	PIN wen[50]
		USE SIGNAL ;
		DIRECTION INPUT ;
		SHAPE ABUTMENT ;
		PORT
			LAYER	M1 ;
			RECT	0 94.65 0.25 94.75 ;
			LAYER	M2 ;
			RECT	0 94.65 0.25 94.75 ;
			LAYER	M3 ;
			RECT	0 94.65 0.25 94.75 ;
		END

		ANTENNAGATEAREA 0.014 ;
		ANTENNADIFFAREA 0.018 ;
		ANTENNAPARTIALMETALAREA 0.025 ;
	END wen[50]

	PIN wen[51]
		USE SIGNAL ;
		DIRECTION INPUT ;
		SHAPE ABUTMENT ;
		PORT
			LAYER	M1 ;
			RECT	0 96.84 0.25 96.94 ;
			LAYER	M2 ;
			RECT	0 96.84 0.25 96.94 ;
			LAYER	M3 ;
			RECT	0 96.84 0.25 96.94 ;
		END

		ANTENNAGATEAREA 0.014 ;
		ANTENNADIFFAREA 0.018 ;
		ANTENNAPARTIALMETALAREA 0.025 ;
	END wen[51]

	PIN wen[52]
		USE SIGNAL ;
		DIRECTION INPUT ;
		SHAPE ABUTMENT ;
		PORT
			LAYER	M1 ;
			RECT	0 97.49 0.25 97.59 ;
			LAYER	M2 ;
			RECT	0 97.49 0.25 97.59 ;
			LAYER	M3 ;
			RECT	0 97.49 0.25 97.59 ;
		END

		ANTENNAGATEAREA 0.014 ;
		ANTENNADIFFAREA 0.018 ;
		ANTENNAPARTIALMETALAREA 0.025 ;
	END wen[52]

	PIN wen[53]
		USE SIGNAL ;
		DIRECTION INPUT ;
		SHAPE ABUTMENT ;
		PORT
			LAYER	M1 ;
			RECT	0 99.68 0.25 99.78 ;
			LAYER	M2 ;
			RECT	0 99.68 0.25 99.78 ;
			LAYER	M3 ;
			RECT	0 99.68 0.25 99.78 ;
		END

		ANTENNAGATEAREA 0.014 ;
		ANTENNADIFFAREA 0.018 ;
		ANTENNAPARTIALMETALAREA 0.025 ;
	END wen[53]

	PIN wen[54]
		USE SIGNAL ;
		DIRECTION INPUT ;
		SHAPE ABUTMENT ;
		PORT
			LAYER	M1 ;
			RECT	0 100.33 0.25 100.43 ;
			LAYER	M2 ;
			RECT	0 100.33 0.25 100.43 ;
			LAYER	M3 ;
			RECT	0 100.33 0.25 100.43 ;
		END

		ANTENNAGATEAREA 0.014 ;
		ANTENNADIFFAREA 0.018 ;
		ANTENNAPARTIALMETALAREA 0.025 ;
	END wen[54]

	PIN wen[55]
		USE SIGNAL ;
		DIRECTION INPUT ;
		SHAPE ABUTMENT ;
		PORT
			LAYER	M1 ;
			RECT	0 102.52 0.25 102.62 ;
			LAYER	M2 ;
			RECT	0 102.52 0.25 102.62 ;
			LAYER	M3 ;
			RECT	0 102.52 0.25 102.62 ;
		END

		ANTENNAGATEAREA 0.014 ;
		ANTENNADIFFAREA 0.018 ;
		ANTENNAPARTIALMETALAREA 0.025 ;
	END wen[55]

	PIN wen[56]
		USE SIGNAL ;
		DIRECTION INPUT ;
		SHAPE ABUTMENT ;
		PORT
			LAYER	M1 ;
			RECT	0 103.17 0.25 103.27 ;
			LAYER	M2 ;
			RECT	0 103.17 0.25 103.27 ;
			LAYER	M3 ;
			RECT	0 103.17 0.25 103.27 ;
		END

		ANTENNAGATEAREA 0.014 ;
		ANTENNADIFFAREA 0.018 ;
		ANTENNAPARTIALMETALAREA 0.025 ;
	END wen[56]

	PIN wen[57]
		USE SIGNAL ;
		DIRECTION INPUT ;
		SHAPE ABUTMENT ;
		PORT
			LAYER	M1 ;
			RECT	0 105.36 0.25 105.46 ;
			LAYER	M2 ;
			RECT	0 105.36 0.25 105.46 ;
			LAYER	M3 ;
			RECT	0 105.36 0.25 105.46 ;
		END

		ANTENNAGATEAREA 0.014 ;
		ANTENNADIFFAREA 0.018 ;
		ANTENNAPARTIALMETALAREA 0.025 ;
	END wen[57]

	PIN wen[58]
		USE SIGNAL ;
		DIRECTION INPUT ;
		SHAPE ABUTMENT ;
		PORT
			LAYER	M1 ;
			RECT	0 106.01 0.25 106.11 ;
			LAYER	M2 ;
			RECT	0 106.01 0.25 106.11 ;
			LAYER	M3 ;
			RECT	0 106.01 0.25 106.11 ;
		END

		ANTENNAGATEAREA 0.014 ;
		ANTENNADIFFAREA 0.018 ;
		ANTENNAPARTIALMETALAREA 0.025 ;
	END wen[58]

	PIN wen[59]
		USE SIGNAL ;
		DIRECTION INPUT ;
		SHAPE ABUTMENT ;
		PORT
			LAYER	M1 ;
			RECT	0 108.2 0.25 108.3 ;
			LAYER	M2 ;
			RECT	0 108.2 0.25 108.3 ;
			LAYER	M3 ;
			RECT	0 108.2 0.25 108.3 ;
		END

		ANTENNAGATEAREA 0.014 ;
		ANTENNADIFFAREA 0.018 ;
		ANTENNAPARTIALMETALAREA 0.025 ;
	END wen[59]

	PIN wen[5]
		USE SIGNAL ;
		DIRECTION INPUT ;
		SHAPE ABUTMENT ;
		PORT
			LAYER	M1 ;
			RECT	0 9.035 0.25 9.135 ;
			LAYER	M2 ;
			RECT	0 9.035 0.25 9.135 ;
			LAYER	M3 ;
			RECT	0 9.035 0.25 9.135 ;
		END

		ANTENNAGATEAREA 0.014 ;
		ANTENNADIFFAREA 0.018 ;
		ANTENNAPARTIALMETALAREA 0.025 ;
	END wen[5]

	PIN wen[60]
		USE SIGNAL ;
		DIRECTION INPUT ;
		SHAPE ABUTMENT ;
		PORT
			LAYER	M1 ;
			RECT	0 108.85 0.25 108.95 ;
			LAYER	M2 ;
			RECT	0 108.85 0.25 108.95 ;
			LAYER	M3 ;
			RECT	0 108.85 0.25 108.95 ;
		END

		ANTENNAGATEAREA 0.014 ;
		ANTENNADIFFAREA 0.018 ;
		ANTENNAPARTIALMETALAREA 0.025 ;
	END wen[60]

	PIN wen[61]
		USE SIGNAL ;
		DIRECTION INPUT ;
		SHAPE ABUTMENT ;
		PORT
			LAYER	M1 ;
			RECT	0 111.04 0.25 111.14 ;
			LAYER	M2 ;
			RECT	0 111.04 0.25 111.14 ;
			LAYER	M3 ;
			RECT	0 111.04 0.25 111.14 ;
		END

		ANTENNAGATEAREA 0.014 ;
		ANTENNADIFFAREA 0.018 ;
		ANTENNAPARTIALMETALAREA 0.025 ;
	END wen[61]

	PIN wen[62]
		USE SIGNAL ;
		DIRECTION INPUT ;
		SHAPE ABUTMENT ;
		PORT
			LAYER	M1 ;
			RECT	0 111.69 0.25 111.79 ;
			LAYER	M2 ;
			RECT	0 111.69 0.25 111.79 ;
			LAYER	M3 ;
			RECT	0 111.69 0.25 111.79 ;
		END

		ANTENNAGATEAREA 0.014 ;
		ANTENNADIFFAREA 0.018 ;
		ANTENNAPARTIALMETALAREA 0.025 ;
	END wen[62]

	PIN wen[63]
		USE SIGNAL ;
		DIRECTION INPUT ;
		SHAPE ABUTMENT ;
		PORT
			LAYER	M1 ;
			RECT	0 113.88 0.25 113.98 ;
			LAYER	M2 ;
			RECT	0 113.88 0.25 113.98 ;
			LAYER	M3 ;
			RECT	0 113.88 0.25 113.98 ;
		END

		ANTENNAGATEAREA 0.014 ;
		ANTENNADIFFAREA 0.018 ;
		ANTENNAPARTIALMETALAREA 0.025 ;
	END wen[63]

	PIN wen[6]
		USE SIGNAL ;
		DIRECTION INPUT ;
		SHAPE ABUTMENT ;
		PORT
			LAYER	M1 ;
			RECT	0 9.685 0.25 9.785 ;
			LAYER	M2 ;
			RECT	0 9.685 0.25 9.785 ;
			LAYER	M3 ;
			RECT	0 9.685 0.25 9.785 ;
		END

		ANTENNAGATEAREA 0.014 ;
		ANTENNADIFFAREA 0.018 ;
		ANTENNAPARTIALMETALAREA 0.025 ;
	END wen[6]

	PIN wen[7]
		USE SIGNAL ;
		DIRECTION INPUT ;
		SHAPE ABUTMENT ;
		PORT
			LAYER	M1 ;
			RECT	0 11.875 0.25 11.975 ;
			LAYER	M2 ;
			RECT	0 11.875 0.25 11.975 ;
			LAYER	M3 ;
			RECT	0 11.875 0.25 11.975 ;
		END

		ANTENNAGATEAREA 0.014 ;
		ANTENNADIFFAREA 0.018 ;
		ANTENNAPARTIALMETALAREA 0.025 ;
	END wen[7]

	PIN wen[8]
		USE SIGNAL ;
		DIRECTION INPUT ;
		SHAPE ABUTMENT ;
		PORT
			LAYER	M1 ;
			RECT	0 12.525 0.25 12.625 ;
			LAYER	M2 ;
			RECT	0 12.525 0.25 12.625 ;
			LAYER	M3 ;
			RECT	0 12.525 0.25 12.625 ;
		END

		ANTENNAGATEAREA 0.014 ;
		ANTENNADIFFAREA 0.018 ;
		ANTENNAPARTIALMETALAREA 0.025 ;
	END wen[8]

	PIN wen[9]
		USE SIGNAL ;
		DIRECTION INPUT ;
		SHAPE ABUTMENT ;
		PORT
			LAYER	M1 ;
			RECT	0 14.715 0.25 14.815 ;
			LAYER	M2 ;
			RECT	0 14.715 0.25 14.815 ;
			LAYER	M3 ;
			RECT	0 14.715 0.25 14.815 ;
		END

		ANTENNAGATEAREA 0.014 ;
		ANTENNADIFFAREA 0.018 ;
		ANTENNAPARTIALMETALAREA 0.025 ;
	END wen[9]

	OBS
		LAYER	M1 DESIGNRULEWIDTH 0.165 ;
		RECT	0.32 0.3 26 114.845 ;
		RECT	0 0 0.32 1.115 ;
		RECT	0 1.515 0.32 1.945 ;
		RECT	0 2.145 0.32 2.475 ;
		RECT	0 2.675 0.32 3.105 ;
		RECT	0 3.505 0.32 3.955 ;
		RECT	0 4.355 0.32 4.785 ;
		RECT	0 4.985 0.32 5.315 ;
		RECT	0 5.515 0.32 5.945 ;
		RECT	0 6.345 0.32 6.795 ;
		RECT	0 7.195 0.32 7.625 ;
		RECT	0 7.825 0.32 8.155 ;
		RECT	0 8.355 0.32 8.785 ;
		RECT	0 9.185 0.32 9.635 ;
		RECT	0 10.035 0.32 10.465 ;
		RECT	0 10.665 0.32 10.995 ;
		RECT	0 11.195 0.32 11.625 ;
		RECT	0 12.025 0.32 12.475 ;
		RECT	0 12.875 0.32 13.305 ;
		RECT	0 13.505 0.32 13.835 ;
		RECT	0 14.035 0.32 14.465 ;
		RECT	0 14.865 0.32 15.315 ;
		RECT	0 15.715 0.32 16.145 ;
		RECT	0 16.345 0.32 16.675 ;
		RECT	0 16.875 0.32 17.305 ;
		RECT	0 17.705 0.32 18.155 ;
		RECT	0 18.555 0.32 18.985 ;
		RECT	0 19.185 0.32 19.515 ;
		RECT	0 19.715 0.32 20.145 ;
		RECT	0 20.545 0.32 20.995 ;
		RECT	0 21.395 0.32 21.825 ;
		RECT	0 22.025 0.32 22.355 ;
		RECT	0 22.555 0.32 22.985 ;
		RECT	0 23.385 0.32 23.835 ;
		RECT	0 24.235 0.32 24.665 ;
		RECT	0 24.865 0.32 25.195 ;
		RECT	0 25.395 0.32 25.825 ;
		RECT	0 26.225 0.32 26.675 ;
		RECT	0 27.075 0.32 27.505 ;
		RECT	0 27.705 0.32 28.035 ;
		RECT	0 28.235 0.32 28.665 ;
		RECT	0 29.065 0.32 29.515 ;
		RECT	0 29.915 0.32 30.345 ;
		RECT	0 30.545 0.32 30.875 ;
		RECT	0 31.075 0.32 31.505 ;
		RECT	0 31.905 0.32 32.355 ;
		RECT	0 32.755 0.32 33.185 ;
		RECT	0 33.385 0.32 33.715 ;
		RECT	0 33.915 0.32 34.345 ;
		RECT	0 34.745 0.32 35.195 ;
		RECT	0 35.595 0.32 36.025 ;
		RECT	0 36.225 0.32 36.555 ;
		RECT	0 36.755 0.32 37.185 ;
		RECT	0 37.585 0.32 38.035 ;
		RECT	0 38.435 0.32 38.865 ;
		RECT	0 39.065 0.32 39.395 ;
		RECT	0 39.595 0.32 40.025 ;
		RECT	0 40.425 0.32 40.875 ;
		RECT	0 41.275 0.32 41.705 ;
		RECT	0 41.905 0.32 42.235 ;
		RECT	0 42.435 0.32 42.865 ;
		RECT	0 43.265 0.32 43.715 ;
		RECT	0 44.115 0.32 44.545 ;
		RECT	0 44.745 0.32 45.075 ;
		RECT	0 45.275 0.32 45.705 ;
		RECT	0 46.105 0.32 48.575 ;
		RECT	0 48.775 0.32 51.02 ;
		RECT	0 51.22 0.32 51.41 ;
		RECT	0 51.61 0.32 52.535 ;
		RECT	0 52.735 0.32 54.4 ;
		RECT	0 54.6 0.32 55 ;
		RECT	0 55.2 0.32 55.4 ;
		RECT	0 55.6 0.32 57.31 ;
		RECT	0 57.51 0.32 57.64 ;
		RECT	0 57.84 0.32 59.745 ;
		RECT	0 59.945 0.32 60.215 ;
		RECT	0 60.815 0.32 66.895 ;
		RECT	0 67.095 0.32 67.27 ;
		RECT	0 67.47 0.32 69.04 ;
		RECT	0 69.44 0.32 69.87 ;
		RECT	0 70.07 0.32 70.4 ;
		RECT	0 70.6 0.32 71.03 ;
		RECT	0 71.43 0.32 71.88 ;
		RECT	0 72.28 0.32 72.71 ;
		RECT	0 72.91 0.32 73.24 ;
		RECT	0 73.44 0.32 73.87 ;
		RECT	0 74.27 0.32 74.72 ;
		RECT	0 75.12 0.32 75.55 ;
		RECT	0 75.75 0.32 76.08 ;
		RECT	0 76.28 0.32 76.71 ;
		RECT	0 77.11 0.32 77.56 ;
		RECT	0 77.96 0.32 78.39 ;
		RECT	0 78.59 0.32 78.92 ;
		RECT	0 79.12 0.32 79.55 ;
		RECT	0 79.95 0.32 80.4 ;
		RECT	0 80.8 0.32 81.23 ;
		RECT	0 81.43 0.32 81.76 ;
		RECT	0 81.96 0.32 82.39 ;
		RECT	0 82.79 0.32 83.24 ;
		RECT	0 83.64 0.32 84.07 ;
		RECT	0 84.27 0.32 84.6 ;
		RECT	0 84.8 0.32 85.23 ;
		RECT	0 85.63 0.32 86.08 ;
		RECT	0 86.48 0.32 86.91 ;
		RECT	0 87.11 0.32 87.44 ;
		RECT	0 87.64 0.32 88.07 ;
		RECT	0 88.47 0.32 88.92 ;
		RECT	0 89.32 0.32 89.75 ;
		RECT	0 89.95 0.32 90.28 ;
		RECT	0 90.48 0.32 90.91 ;
		RECT	0 91.31 0.32 91.76 ;
		RECT	0 92.16 0.32 92.59 ;
		RECT	0 92.79 0.32 93.12 ;
		RECT	0 93.32 0.32 93.75 ;
		RECT	0 94.15 0.32 94.6 ;
		RECT	0 95 0.32 95.43 ;
		RECT	0 95.63 0.32 95.96 ;
		RECT	0 96.16 0.32 96.59 ;
		RECT	0 96.99 0.32 97.44 ;
		RECT	0 97.84 0.32 98.27 ;
		RECT	0 98.47 0.32 98.8 ;
		RECT	0 99 0.32 99.43 ;
		RECT	0 99.83 0.32 100.28 ;
		RECT	0 100.68 0.32 101.11 ;
		RECT	0 101.31 0.32 101.64 ;
		RECT	0 101.84 0.32 102.27 ;
		RECT	0 102.67 0.32 103.12 ;
		RECT	0 103.52 0.32 103.95 ;
		RECT	0 104.15 0.32 104.48 ;
		RECT	0 104.68 0.32 105.11 ;
		RECT	0 105.51 0.32 105.96 ;
		RECT	0 106.36 0.32 106.79 ;
		RECT	0 106.99 0.32 107.32 ;
		RECT	0 107.52 0.32 107.95 ;
		RECT	0 108.35 0.32 108.8 ;
		RECT	0 109.2 0.32 109.63 ;
		RECT	0 109.83 0.32 110.16 ;
		RECT	0 110.36 0.32 110.79 ;
		RECT	0 111.19 0.32 111.64 ;
		RECT	0 112.04 0.32 112.47 ;
		RECT	0 112.67 0.32 113 ;
		RECT	0 113.2 0.32 113.63 ;
		RECT	0 114.03 0.32 115.145 ;
		RECT	26 0 26.32 115.145 ;
		RECT	0.32 0 26 0.3 ;
		RECT	0.32 114.845 26 115.145 ;
		LAYER	M2 DESIGNRULEWIDTH 0.165 ;
		RECT	0.32 0.3 26 114.845 ;
		RECT	0 0 0.32 1.115 ;
		RECT	0 1.515 0.32 1.945 ;
		RECT	0 2.145 0.32 2.475 ;
		RECT	0 2.675 0.32 3.105 ;
		RECT	0 3.505 0.32 3.955 ;
		RECT	0 4.355 0.32 4.785 ;
		RECT	0 4.985 0.32 5.315 ;
		RECT	0 5.515 0.32 5.945 ;
		RECT	0 6.345 0.32 6.795 ;
		RECT	0 7.195 0.32 7.625 ;
		RECT	0 7.825 0.32 8.155 ;
		RECT	0 8.355 0.32 8.785 ;
		RECT	0 9.185 0.32 9.635 ;
		RECT	0 10.035 0.32 10.465 ;
		RECT	0 10.665 0.32 10.995 ;
		RECT	0 11.195 0.32 11.625 ;
		RECT	0 12.025 0.32 12.475 ;
		RECT	0 12.875 0.32 13.305 ;
		RECT	0 13.505 0.32 13.835 ;
		RECT	0 14.035 0.32 14.465 ;
		RECT	0 14.865 0.32 15.315 ;
		RECT	0 15.715 0.32 16.145 ;
		RECT	0 16.345 0.32 16.675 ;
		RECT	0 16.875 0.32 17.305 ;
		RECT	0 17.705 0.32 18.155 ;
		RECT	0 18.555 0.32 18.985 ;
		RECT	0 19.185 0.32 19.515 ;
		RECT	0 19.715 0.32 20.145 ;
		RECT	0 20.545 0.32 20.995 ;
		RECT	0 21.395 0.32 21.825 ;
		RECT	0 22.025 0.32 22.355 ;
		RECT	0 22.555 0.32 22.985 ;
		RECT	0 23.385 0.32 23.835 ;
		RECT	0 24.235 0.32 24.665 ;
		RECT	0 24.865 0.32 25.195 ;
		RECT	0 25.395 0.32 25.825 ;
		RECT	0 26.225 0.32 26.675 ;
		RECT	0 27.075 0.32 27.505 ;
		RECT	0 27.705 0.32 28.035 ;
		RECT	0 28.235 0.32 28.665 ;
		RECT	0 29.065 0.32 29.515 ;
		RECT	0 29.915 0.32 30.345 ;
		RECT	0 30.545 0.32 30.875 ;
		RECT	0 31.075 0.32 31.505 ;
		RECT	0 31.905 0.32 32.355 ;
		RECT	0 32.755 0.32 33.185 ;
		RECT	0 33.385 0.32 33.715 ;
		RECT	0 33.915 0.32 34.345 ;
		RECT	0 34.745 0.32 35.195 ;
		RECT	0 35.595 0.32 36.025 ;
		RECT	0 36.225 0.32 36.555 ;
		RECT	0 36.755 0.32 37.185 ;
		RECT	0 37.585 0.32 38.035 ;
		RECT	0 38.435 0.32 38.865 ;
		RECT	0 39.065 0.32 39.395 ;
		RECT	0 39.595 0.32 40.025 ;
		RECT	0 40.425 0.32 40.875 ;
		RECT	0 41.275 0.32 41.705 ;
		RECT	0 41.905 0.32 42.235 ;
		RECT	0 42.435 0.32 42.865 ;
		RECT	0 43.265 0.32 43.715 ;
		RECT	0 44.115 0.32 44.545 ;
		RECT	0 44.745 0.32 45.075 ;
		RECT	0 45.275 0.32 45.705 ;
		RECT	0 46.105 0.32 48.575 ;
		RECT	0 48.775 0.32 51.02 ;
		RECT	0 51.22 0.32 51.41 ;
		RECT	0 51.61 0.32 52.535 ;
		RECT	0 52.735 0.32 54.205 ;
		RECT	0 54.6 0.32 55 ;
		RECT	0 55.2 0.32 55.4 ;
		RECT	0 55.6 0.32 57.31 ;
		RECT	0 57.51 0.32 57.64 ;
		RECT	0 57.84 0.32 59.745 ;
		RECT	0 59.945 0.32 60.215 ;
		RECT	0 60.815 0.32 66.895 ;
		RECT	0 67.095 0.32 67.27 ;
		RECT	0 67.47 0.32 69.04 ;
		RECT	0 69.44 0.32 69.87 ;
		RECT	0 70.07 0.32 70.4 ;
		RECT	0 70.6 0.32 71.03 ;
		RECT	0 71.43 0.32 71.88 ;
		RECT	0 72.28 0.32 72.71 ;
		RECT	0 72.91 0.32 73.24 ;
		RECT	0 73.44 0.32 73.87 ;
		RECT	0 74.27 0.32 74.72 ;
		RECT	0 75.12 0.32 75.55 ;
		RECT	0 75.75 0.32 76.08 ;
		RECT	0 76.28 0.32 76.71 ;
		RECT	0 77.11 0.32 77.56 ;
		RECT	0 77.96 0.32 78.39 ;
		RECT	0 78.59 0.32 78.92 ;
		RECT	0 79.12 0.32 79.55 ;
		RECT	0 79.95 0.32 80.4 ;
		RECT	0 80.8 0.32 81.23 ;
		RECT	0 81.43 0.32 81.76 ;
		RECT	0 81.96 0.32 82.39 ;
		RECT	0 82.79 0.32 83.24 ;
		RECT	0 83.64 0.32 84.07 ;
		RECT	0 84.27 0.32 84.6 ;
		RECT	0 84.8 0.32 85.23 ;
		RECT	0 85.63 0.32 86.08 ;
		RECT	0 86.48 0.32 86.91 ;
		RECT	0 87.11 0.32 87.44 ;
		RECT	0 87.64 0.32 88.07 ;
		RECT	0 88.47 0.32 88.92 ;
		RECT	0 89.32 0.32 89.75 ;
		RECT	0 89.95 0.32 90.28 ;
		RECT	0 90.48 0.32 90.91 ;
		RECT	0 91.31 0.32 91.76 ;
		RECT	0 92.16 0.32 92.59 ;
		RECT	0 92.79 0.32 93.12 ;
		RECT	0 93.32 0.32 93.75 ;
		RECT	0 94.15 0.32 94.6 ;
		RECT	0 95 0.32 95.43 ;
		RECT	0 95.63 0.32 95.96 ;
		RECT	0 96.16 0.32 96.59 ;
		RECT	0 96.99 0.32 97.44 ;
		RECT	0 97.84 0.32 98.27 ;
		RECT	0 98.47 0.32 98.8 ;
		RECT	0 99 0.32 99.43 ;
		RECT	0 99.83 0.32 100.28 ;
		RECT	0 100.68 0.32 101.11 ;
		RECT	0 101.31 0.32 101.64 ;
		RECT	0 101.84 0.32 102.27 ;
		RECT	0 102.67 0.32 103.12 ;
		RECT	0 103.52 0.32 103.95 ;
		RECT	0 104.15 0.32 104.48 ;
		RECT	0 104.68 0.32 105.11 ;
		RECT	0 105.51 0.32 105.96 ;
		RECT	0 106.36 0.32 106.79 ;
		RECT	0 106.99 0.32 107.32 ;
		RECT	0 107.52 0.32 107.95 ;
		RECT	0 108.35 0.32 108.8 ;
		RECT	0 109.2 0.32 109.63 ;
		RECT	0 109.83 0.32 110.16 ;
		RECT	0 110.36 0.32 110.79 ;
		RECT	0 111.19 0.32 111.64 ;
		RECT	0 112.04 0.32 112.47 ;
		RECT	0 112.67 0.32 113 ;
		RECT	0 113.2 0.32 113.63 ;
		RECT	0 114.03 0.32 115.145 ;
		RECT	26 0 26.32 115.145 ;
		RECT	0.32 0 26 0.3 ;
		RECT	0.32 114.845 26 115.145 ;
		LAYER	M3 DESIGNRULEWIDTH 0.165 ;
		RECT	0.32 0.3 26 114.845 ;
		RECT	0 0 0.32 1.115 ;
		RECT	0 1.515 0.32 1.945 ;
		RECT	0 2.145 0.32 2.475 ;
		RECT	0 2.675 0.32 3.105 ;
		RECT	0 3.505 0.32 3.955 ;
		RECT	0 4.355 0.32 4.785 ;
		RECT	0 4.985 0.32 5.315 ;
		RECT	0 5.515 0.32 5.945 ;
		RECT	0 6.345 0.32 6.795 ;
		RECT	0 7.195 0.32 7.625 ;
		RECT	0 7.825 0.32 8.155 ;
		RECT	0 8.355 0.32 8.785 ;
		RECT	0 9.185 0.32 9.635 ;
		RECT	0 10.035 0.32 10.465 ;
		RECT	0 10.665 0.32 10.995 ;
		RECT	0 11.195 0.32 11.625 ;
		RECT	0 12.025 0.32 12.475 ;
		RECT	0 12.875 0.32 13.305 ;
		RECT	0 13.505 0.32 13.835 ;
		RECT	0 14.035 0.32 14.465 ;
		RECT	0 14.865 0.32 15.315 ;
		RECT	0 15.715 0.32 16.145 ;
		RECT	0 16.345 0.32 16.675 ;
		RECT	0 16.875 0.32 17.305 ;
		RECT	0 17.705 0.32 18.155 ;
		RECT	0 18.555 0.32 18.985 ;
		RECT	0 19.185 0.32 19.515 ;
		RECT	0 19.715 0.32 20.145 ;
		RECT	0 20.545 0.32 20.995 ;
		RECT	0 21.395 0.32 21.825 ;
		RECT	0 22.025 0.32 22.355 ;
		RECT	0 22.555 0.32 22.985 ;
		RECT	0 23.385 0.32 23.835 ;
		RECT	0 24.235 0.32 24.665 ;
		RECT	0 24.865 0.32 25.195 ;
		RECT	0 25.395 0.32 25.825 ;
		RECT	0 26.225 0.32 26.675 ;
		RECT	0 27.075 0.32 27.505 ;
		RECT	0 27.705 0.32 28.035 ;
		RECT	0 28.235 0.32 28.665 ;
		RECT	0 29.065 0.32 29.515 ;
		RECT	0 29.915 0.32 30.345 ;
		RECT	0 30.545 0.32 30.875 ;
		RECT	0 31.075 0.32 31.505 ;
		RECT	0 31.905 0.32 32.355 ;
		RECT	0 32.755 0.32 33.185 ;
		RECT	0 33.385 0.32 33.715 ;
		RECT	0 33.915 0.32 34.345 ;
		RECT	0 34.745 0.32 35.195 ;
		RECT	0 35.595 0.32 36.025 ;
		RECT	0 36.225 0.32 36.555 ;
		RECT	0 36.755 0.32 37.185 ;
		RECT	0 37.585 0.32 38.035 ;
		RECT	0 38.435 0.32 38.865 ;
		RECT	0 39.065 0.32 39.395 ;
		RECT	0 39.595 0.32 40.025 ;
		RECT	0 40.425 0.32 40.875 ;
		RECT	0 41.275 0.32 41.705 ;
		RECT	0 41.905 0.32 42.235 ;
		RECT	0 42.435 0.32 42.865 ;
		RECT	0 43.265 0.32 43.715 ;
		RECT	0 44.115 0.32 44.545 ;
		RECT	0 44.745 0.32 45.075 ;
		RECT	0 45.275 0.32 45.705 ;
		RECT	0 46.105 0.32 48.575 ;
		RECT	0 48.775 0.32 51.02 ;
		RECT	0 51.22 0.32 51.41 ;
		RECT	0 51.61 0.32 52.535 ;
		RECT	0 52.735 0.32 54.205 ;
		RECT	0 54.6 0.32 55 ;
		RECT	0 55.2 0.32 55.4 ;
		RECT	0 55.6 0.32 57.31 ;
		RECT	0 57.51 0.32 57.64 ;
		RECT	0 57.84 0.32 59.745 ;
		RECT	0 59.945 0.32 60.215 ;
		RECT	0 60.815 0.32 66.895 ;
		RECT	0 67.095 0.32 67.27 ;
		RECT	0 67.47 0.32 69.04 ;
		RECT	0 69.44 0.32 69.87 ;
		RECT	0 70.07 0.32 70.4 ;
		RECT	0 70.6 0.32 71.03 ;
		RECT	0 71.43 0.32 71.88 ;
		RECT	0 72.28 0.32 72.71 ;
		RECT	0 72.91 0.32 73.24 ;
		RECT	0 73.44 0.32 73.87 ;
		RECT	0 74.27 0.32 74.72 ;
		RECT	0 75.12 0.32 75.55 ;
		RECT	0 75.75 0.32 76.08 ;
		RECT	0 76.28 0.32 76.71 ;
		RECT	0 77.11 0.32 77.56 ;
		RECT	0 77.96 0.32 78.39 ;
		RECT	0 78.59 0.32 78.92 ;
		RECT	0 79.12 0.32 79.55 ;
		RECT	0 79.95 0.32 80.4 ;
		RECT	0 80.8 0.32 81.23 ;
		RECT	0 81.43 0.32 81.76 ;
		RECT	0 81.96 0.32 82.39 ;
		RECT	0 82.79 0.32 83.24 ;
		RECT	0 83.64 0.32 84.07 ;
		RECT	0 84.27 0.32 84.6 ;
		RECT	0 84.8 0.32 85.23 ;
		RECT	0 85.63 0.32 86.08 ;
		RECT	0 86.48 0.32 86.91 ;
		RECT	0 87.11 0.32 87.44 ;
		RECT	0 87.64 0.32 88.07 ;
		RECT	0 88.47 0.32 88.92 ;
		RECT	0 89.32 0.32 89.75 ;
		RECT	0 89.95 0.32 90.28 ;
		RECT	0 90.48 0.32 90.91 ;
		RECT	0 91.31 0.32 91.76 ;
		RECT	0 92.16 0.32 92.59 ;
		RECT	0 92.79 0.32 93.12 ;
		RECT	0 93.32 0.32 93.75 ;
		RECT	0 94.15 0.32 94.6 ;
		RECT	0 95 0.32 95.43 ;
		RECT	0 95.63 0.32 95.96 ;
		RECT	0 96.16 0.32 96.59 ;
		RECT	0 96.99 0.32 97.44 ;
		RECT	0 97.84 0.32 98.27 ;
		RECT	0 98.47 0.32 98.8 ;
		RECT	0 99 0.32 99.43 ;
		RECT	0 99.83 0.32 100.28 ;
		RECT	0 100.68 0.32 101.11 ;
		RECT	0 101.31 0.32 101.64 ;
		RECT	0 101.84 0.32 102.27 ;
		RECT	0 102.67 0.32 103.12 ;
		RECT	0 103.52 0.32 103.95 ;
		RECT	0 104.15 0.32 104.48 ;
		RECT	0 104.68 0.32 105.11 ;
		RECT	0 105.51 0.32 105.96 ;
		RECT	0 106.36 0.32 106.79 ;
		RECT	0 106.99 0.32 107.32 ;
		RECT	0 107.52 0.32 107.95 ;
		RECT	0 108.35 0.32 108.8 ;
		RECT	0 109.2 0.32 109.63 ;
		RECT	0 109.83 0.32 110.16 ;
		RECT	0 110.36 0.32 110.79 ;
		RECT	0 111.19 0.32 111.64 ;
		RECT	0 112.04 0.32 112.47 ;
		RECT	0 112.67 0.32 113 ;
		RECT	0 113.2 0.32 113.63 ;
		RECT	0 114.03 0.32 115.145 ;
		RECT	26 0 26.32 115.145 ;
		RECT	0.32 0 26 0.3 ;
		RECT	0.32 114.845 26 115.145 ;
		LAYER	M4 DESIGNRULEWIDTH 0.165 ;
		RECT	0.32 0 26 0.09 ;
		RECT	0 0 0.32 0.09 ;
		RECT	26 0 26.32 0.09 ;
		RECT	0.32 0.9 26 1.48 ;
		RECT	0 0.9 0.32 1.48 ;
		RECT	26 0.9 26.32 1.48 ;
		RECT	0.32 2.2 26 2.37 ;
		RECT	0 2.2 0.32 2.37 ;
		RECT	26 2.2 26.32 2.37 ;
		RECT	0.32 2.78 26 2.83 ;
		RECT	0 2.78 0.32 2.83 ;
		RECT	26 2.78 26.32 2.83 ;
		RECT	0.32 3.63 26 4.32 ;
		RECT	0 3.63 0.32 4.32 ;
		RECT	26 3.63 26.32 4.32 ;
		RECT	0.32 5.04 26 5.21 ;
		RECT	0 5.04 0.32 5.21 ;
		RECT	26 5.04 26.32 5.21 ;
		RECT	0.32 5.62 26 5.67 ;
		RECT	0 5.62 0.32 5.67 ;
		RECT	26 5.62 26.32 5.67 ;
		RECT	0.32 6.47 26 7.16 ;
		RECT	0 6.47 0.32 7.16 ;
		RECT	26 6.47 26.32 7.16 ;
		RECT	0.32 7.88 26 8.05 ;
		RECT	0 7.88 0.32 8.05 ;
		RECT	26 7.88 26.32 8.05 ;
		RECT	0.32 8.46 26 8.51 ;
		RECT	0 8.46 0.32 8.51 ;
		RECT	26 8.46 26.32 8.51 ;
		RECT	0.32 9.31 26 10 ;
		RECT	0 9.31 0.32 10 ;
		RECT	26 9.31 26.32 10 ;
		RECT	0.32 10.72 26 10.89 ;
		RECT	0 10.72 0.32 10.89 ;
		RECT	26 10.72 26.32 10.89 ;
		RECT	0.32 11.3 26 11.35 ;
		RECT	0 11.3 0.32 11.35 ;
		RECT	26 11.3 26.32 11.35 ;
		RECT	0.32 12.15 26 12.84 ;
		RECT	0 12.15 0.32 12.84 ;
		RECT	26 12.15 26.32 12.84 ;
		RECT	0.32 13.56 26 13.73 ;
		RECT	0 13.56 0.32 13.73 ;
		RECT	26 13.56 26.32 13.73 ;
		RECT	0.32 14.14 26 14.19 ;
		RECT	0 14.14 0.32 14.19 ;
		RECT	26 14.14 26.32 14.19 ;
		RECT	0.32 14.99 26 15.68 ;
		RECT	0 14.99 0.32 15.68 ;
		RECT	26 14.99 26.32 15.68 ;
		RECT	0.32 16.4 26 16.57 ;
		RECT	0 16.4 0.32 16.57 ;
		RECT	26 16.4 26.32 16.57 ;
		RECT	0.32 16.98 26 17.03 ;
		RECT	0 16.98 0.32 17.03 ;
		RECT	26 16.98 26.32 17.03 ;
		RECT	0.32 17.83 26 18.52 ;
		RECT	0 17.83 0.32 18.52 ;
		RECT	26 17.83 26.32 18.52 ;
		RECT	0.32 19.24 26 19.41 ;
		RECT	0 19.24 0.32 19.41 ;
		RECT	26 19.24 26.32 19.41 ;
		RECT	0.32 19.82 26 19.87 ;
		RECT	0 19.82 0.32 19.87 ;
		RECT	26 19.82 26.32 19.87 ;
		RECT	0.32 20.67 26 21.36 ;
		RECT	0 20.67 0.32 21.36 ;
		RECT	26 20.67 26.32 21.36 ;
		RECT	0.32 22.08 26 22.25 ;
		RECT	0 22.08 0.32 22.25 ;
		RECT	26 22.08 26.32 22.25 ;
		RECT	0.32 22.66 26 22.71 ;
		RECT	0 22.66 0.32 22.71 ;
		RECT	26 22.66 26.32 22.71 ;
		RECT	0.32 23.51 26 24.2 ;
		RECT	0 23.51 0.32 24.2 ;
		RECT	26 23.51 26.32 24.2 ;
		RECT	0.32 24.92 26 25.09 ;
		RECT	0 24.92 0.32 25.09 ;
		RECT	26 24.92 26.32 25.09 ;
		RECT	0.32 25.5 26 25.55 ;
		RECT	0 25.5 0.32 25.55 ;
		RECT	26 25.5 26.32 25.55 ;
		RECT	0.32 26.35 26 27.04 ;
		RECT	0 26.35 0.32 27.04 ;
		RECT	26 26.35 26.32 27.04 ;
		RECT	0.32 27.76 26 27.93 ;
		RECT	0 27.76 0.32 27.93 ;
		RECT	26 27.76 26.32 27.93 ;
		RECT	0.32 28.34 26 28.39 ;
		RECT	0 28.34 0.32 28.39 ;
		RECT	26 28.34 26.32 28.39 ;
		RECT	0.32 29.19 26 29.88 ;
		RECT	0 29.19 0.32 29.88 ;
		RECT	26 29.19 26.32 29.88 ;
		RECT	0.32 30.6 26 30.77 ;
		RECT	0 30.6 0.32 30.77 ;
		RECT	26 30.6 26.32 30.77 ;
		RECT	0.32 31.18 26 31.23 ;
		RECT	0 31.18 0.32 31.23 ;
		RECT	26 31.18 26.32 31.23 ;
		RECT	0.32 32.03 26 32.72 ;
		RECT	0 32.03 0.32 32.72 ;
		RECT	26 32.03 26.32 32.72 ;
		RECT	0.32 33.44 26 33.61 ;
		RECT	0 33.44 0.32 33.61 ;
		RECT	26 33.44 26.32 33.61 ;
		RECT	0.32 34.02 26 34.07 ;
		RECT	0 34.02 0.32 34.07 ;
		RECT	26 34.02 26.32 34.07 ;
		RECT	0.32 34.87 26 35.56 ;
		RECT	0 34.87 0.32 35.56 ;
		RECT	26 34.87 26.32 35.56 ;
		RECT	0.32 36.28 26 36.45 ;
		RECT	0 36.28 0.32 36.45 ;
		RECT	26 36.28 26.32 36.45 ;
		RECT	0.32 36.86 26 36.91 ;
		RECT	0 36.86 0.32 36.91 ;
		RECT	26 36.86 26.32 36.91 ;
		RECT	0.32 37.71 26 38.4 ;
		RECT	0 37.71 0.32 38.4 ;
		RECT	26 37.71 26.32 38.4 ;
		RECT	0.32 39.12 26 39.29 ;
		RECT	0 39.12 0.32 39.29 ;
		RECT	26 39.12 26.32 39.29 ;
		RECT	0.32 39.7 26 39.75 ;
		RECT	0 39.7 0.32 39.75 ;
		RECT	26 39.7 26.32 39.75 ;
		RECT	0.32 40.55 26 41.24 ;
		RECT	0 40.55 0.32 41.24 ;
		RECT	26 40.55 26.32 41.24 ;
		RECT	0.32 41.96 26 42.13 ;
		RECT	0 41.96 0.32 42.13 ;
		RECT	26 41.96 26.32 42.13 ;
		RECT	0.32 42.54 26 42.59 ;
		RECT	0 42.54 0.32 42.59 ;
		RECT	26 42.54 26.32 42.59 ;
		RECT	0.32 43.39 26 44.08 ;
		RECT	0 43.39 0.32 44.08 ;
		RECT	26 43.39 26.32 44.08 ;
		RECT	0.32 44.8 26 44.97 ;
		RECT	0 44.8 0.32 44.97 ;
		RECT	26 44.8 26.32 44.97 ;
		RECT	0.32 45.38 26 45.43 ;
		RECT	0 45.38 0.32 45.43 ;
		RECT	26 45.38 26.32 45.43 ;
		RECT	0.32 46.23 26 46.745 ;
		RECT	0 46.23 0.32 46.745 ;
		RECT	26 46.23 26.32 46.745 ;
		RECT	0.32 47.395 26 47.49 ;
		RECT	0 47.395 0.32 47.49 ;
		RECT	26 47.395 26.32 47.49 ;
		RECT	0.32 47.72 26 47.85 ;
		RECT	0 47.72 0.32 47.85 ;
		RECT	26 47.72 26.32 47.85 ;
		RECT	0.32 48.26 26 48.735 ;
		RECT	0 48.26 0.32 48.735 ;
		RECT	26 48.26 26.32 48.735 ;
		RECT	0.32 49.84 26 50.175 ;
		RECT	0 49.84 0.32 50.175 ;
		RECT	26 49.84 26.32 50.175 ;
		RECT	0.32 50.835 26 51.24 ;
		RECT	0 50.835 0.32 51.02 ;
		RECT	26 50.835 26.32 51.24 ;
		RECT	0.32 51.55 26 51.635 ;
		RECT	0 51.55 0.32 51.635 ;
		RECT	26 51.55 26.32 51.635 ;
		RECT	0.32 51.865 26 52.345 ;
		RECT	0 51.865 0.32 52.345 ;
		RECT	26 51.865 26.32 52.345 ;
		RECT	0.32 53.02 26 53.085 ;
		RECT	0 53.02 0.32 53.085 ;
		RECT	26 53.02 26.32 53.085 ;
		RECT	0.32 53.495 26 53.935 ;
		RECT	0 53.495 0.32 53.935 ;
		RECT	26 53.495 26.32 53.935 ;
		RECT	0.32 54.165 26 54.5 ;
		RECT	0 54.165 0.32 54.5 ;
		RECT	26 54.165 26.32 54.5 ;
		RECT	0.32 54.91 26 55.055 ;
		RECT	0 54.91 0.32 55.055 ;
		RECT	26 54.91 26.32 55.055 ;
		RECT	0.32 55.975 26 57.09 ;
		RECT	0 55.975 0.32 57.09 ;
		RECT	26 55.975 26.32 57.09 ;
		RECT	0.32 57.5 26 58.06 ;
		RECT	0 57.5 0.32 58.06 ;
		RECT	26 57.5 26.32 58.06 ;
		RECT	0.32 58.47 26 59.62 ;
		RECT	0 58.47 0.32 59.62 ;
		RECT	26 58.47 26.32 59.62 ;
		RECT	0.32 60.24 26 60.48 ;
		RECT	0 60.24 0.32 60.48 ;
		RECT	26 60.24 26.32 60.48 ;
		RECT	0.32 60.89 26 61.2 ;
		RECT	0 60.89 0.32 61.2 ;
		RECT	26 60.89 26.32 61.2 ;
		RECT	0.32 61.43 26 61.51 ;
		RECT	0 61.43 0.32 61.51 ;
		RECT	26 61.43 26.32 61.51 ;
		RECT	0.32 61.92 26 62.275 ;
		RECT	0 61.92 0.32 62.275 ;
		RECT	26 61.92 26.32 62.275 ;
		RECT	0.32 62.935 26 63.115 ;
		RECT	0 62.935 0.32 63.115 ;
		RECT	26 62.935 26.32 63.115 ;
		RECT	0.32 63.525 26 63.59 ;
		RECT	0 63.525 0.32 63.59 ;
		RECT	26 63.525 26.32 63.59 ;
		RECT	0.32 64 26 64.155 ;
		RECT	0 64 0.32 64.155 ;
		RECT	26 64 26.32 64.155 ;
		RECT	0.32 64.465 26 64.855 ;
		RECT	0 64.465 0.32 64.855 ;
		RECT	26 64.465 26.32 64.855 ;
		RECT	0.32 65.265 26 65.395 ;
		RECT	0 65.265 0.32 65.395 ;
		RECT	26 65.265 26.32 65.395 ;
		RECT	0.32 65.625 26 66.05 ;
		RECT	0 65.625 0.32 66.05 ;
		RECT	26 65.625 26.32 66.05 ;
		RECT	0.32 66.46 26 66.57 ;
		RECT	0 66.46 0.32 66.57 ;
		RECT	26 66.46 26.32 66.57 ;
		RECT	0.32 67.355 26 67.415 ;
		RECT	0 67.355 0.32 67.415 ;
		RECT	26 67.355 26.32 67.415 ;
		RECT	0.32 68.07 26 68.16 ;
		RECT	0 68.07 0.32 68.16 ;
		RECT	26 68.07 26.32 68.16 ;
		RECT	0.32 68.81 26 68.915 ;
		RECT	0 68.81 0.32 68.915 ;
		RECT	26 68.81 26.32 68.915 ;
		RECT	0.32 69.715 26 69.765 ;
		RECT	0 69.715 0.32 69.765 ;
		RECT	26 69.715 26.32 69.765 ;
		RECT	0.32 70.175 26 70.345 ;
		RECT	0 70.175 0.32 70.345 ;
		RECT	26 70.175 26.32 70.345 ;
		RECT	0.32 71.065 26 71.755 ;
		RECT	0 71.065 0.32 71.755 ;
		RECT	26 71.065 26.32 71.755 ;
		RECT	0.32 72.555 26 72.605 ;
		RECT	0 72.555 0.32 72.605 ;
		RECT	26 72.555 26.32 72.605 ;
		RECT	0.32 73.015 26 73.185 ;
		RECT	0 73.015 0.32 73.185 ;
		RECT	26 73.015 26.32 73.185 ;
		RECT	0.32 73.905 26 74.595 ;
		RECT	0 73.905 0.32 74.595 ;
		RECT	26 73.905 26.32 74.595 ;
		RECT	0.32 75.395 26 75.445 ;
		RECT	0 75.395 0.32 75.445 ;
		RECT	26 75.395 26.32 75.445 ;
		RECT	0.32 75.855 26 76.025 ;
		RECT	0 75.855 0.32 76.025 ;
		RECT	26 75.855 26.32 76.025 ;
		RECT	0.32 76.745 26 77.435 ;
		RECT	0 76.745 0.32 77.435 ;
		RECT	26 76.745 26.32 77.435 ;
		RECT	0.32 78.235 26 78.285 ;
		RECT	0 78.235 0.32 78.285 ;
		RECT	26 78.235 26.32 78.285 ;
		RECT	0.32 78.695 26 78.865 ;
		RECT	0 78.695 0.32 78.865 ;
		RECT	26 78.695 26.32 78.865 ;
		RECT	0.32 79.585 26 80.275 ;
		RECT	0 79.585 0.32 80.275 ;
		RECT	26 79.585 26.32 80.275 ;
		RECT	0.32 81.075 26 81.125 ;
		RECT	0 81.075 0.32 81.125 ;
		RECT	26 81.075 26.32 81.125 ;
		RECT	0.32 81.535 26 81.705 ;
		RECT	0 81.535 0.32 81.705 ;
		RECT	26 81.535 26.32 81.705 ;
		RECT	0.32 82.425 26 83.115 ;
		RECT	0 82.425 0.32 83.115 ;
		RECT	26 82.425 26.32 83.115 ;
		RECT	0.32 83.915 26 83.965 ;
		RECT	0 83.915 0.32 83.965 ;
		RECT	26 83.915 26.32 83.965 ;
		RECT	0.32 84.375 26 84.545 ;
		RECT	0 84.375 0.32 84.545 ;
		RECT	26 84.375 26.32 84.545 ;
		RECT	0.32 85.265 26 85.955 ;
		RECT	0 85.265 0.32 85.955 ;
		RECT	26 85.265 26.32 85.955 ;
		RECT	0.32 86.755 26 86.805 ;
		RECT	0 86.755 0.32 86.805 ;
		RECT	26 86.755 26.32 86.805 ;
		RECT	0.32 87.215 26 87.385 ;
		RECT	0 87.215 0.32 87.385 ;
		RECT	26 87.215 26.32 87.385 ;
		RECT	0.32 88.105 26 88.795 ;
		RECT	0 88.105 0.32 88.795 ;
		RECT	26 88.105 26.32 88.795 ;
		RECT	0.32 89.595 26 89.645 ;
		RECT	0 89.595 0.32 89.645 ;
		RECT	26 89.595 26.32 89.645 ;
		RECT	0.32 90.055 26 90.225 ;
		RECT	0 90.055 0.32 90.225 ;
		RECT	26 90.055 26.32 90.225 ;
		RECT	0.32 90.945 26 91.635 ;
		RECT	0 90.945 0.32 91.635 ;
		RECT	26 90.945 26.32 91.635 ;
		RECT	0.32 92.435 26 92.485 ;
		RECT	0 92.435 0.32 92.485 ;
		RECT	26 92.435 26.32 92.485 ;
		RECT	0.32 92.895 26 93.065 ;
		RECT	0 92.895 0.32 93.065 ;
		RECT	26 92.895 26.32 93.065 ;
		RECT	0.32 93.785 26 94.475 ;
		RECT	0 93.785 0.32 94.475 ;
		RECT	26 93.785 26.32 94.475 ;
		RECT	0.32 95.275 26 95.325 ;
		RECT	0 95.275 0.32 95.325 ;
		RECT	26 95.275 26.32 95.325 ;
		RECT	0.32 95.735 26 95.905 ;
		RECT	0 95.735 0.32 95.905 ;
		RECT	26 95.735 26.32 95.905 ;
		RECT	0.32 96.625 26 97.315 ;
		RECT	0 96.625 0.32 97.315 ;
		RECT	26 96.625 26.32 97.315 ;
		RECT	0.32 98.115 26 98.165 ;
		RECT	0 98.115 0.32 98.165 ;
		RECT	26 98.115 26.32 98.165 ;
		RECT	0.32 98.575 26 98.745 ;
		RECT	0 98.575 0.32 98.745 ;
		RECT	26 98.575 26.32 98.745 ;
		RECT	0.32 99.465 26 100.155 ;
		RECT	0 99.465 0.32 100.155 ;
		RECT	26 99.465 26.32 100.155 ;
		RECT	0.32 100.955 26 101.005 ;
		RECT	0 100.955 0.32 101.005 ;
		RECT	26 100.955 26.32 101.005 ;
		RECT	0.32 101.415 26 101.585 ;
		RECT	0 101.415 0.32 101.585 ;
		RECT	26 101.415 26.32 101.585 ;
		RECT	0.32 102.305 26 102.995 ;
		RECT	0 102.305 0.32 102.995 ;
		RECT	26 102.305 26.32 102.995 ;
		RECT	0.32 103.795 26 103.845 ;
		RECT	0 103.795 0.32 103.845 ;
		RECT	26 103.795 26.32 103.845 ;
		RECT	0.32 104.255 26 104.425 ;
		RECT	0 104.255 0.32 104.425 ;
		RECT	26 104.255 26.32 104.425 ;
		RECT	0.32 105.145 26 105.835 ;
		RECT	0 105.145 0.32 105.835 ;
		RECT	26 105.145 26.32 105.835 ;
		RECT	0.32 106.635 26 106.685 ;
		RECT	0 106.635 0.32 106.685 ;
		RECT	26 106.635 26.32 106.685 ;
		RECT	0.32 107.095 26 107.265 ;
		RECT	0 107.095 0.32 107.265 ;
		RECT	26 107.095 26.32 107.265 ;
		RECT	0.32 107.985 26 108.675 ;
		RECT	0 107.985 0.32 108.675 ;
		RECT	26 107.985 26.32 108.675 ;
		RECT	0.32 109.475 26 109.525 ;
		RECT	0 109.475 0.32 109.525 ;
		RECT	26 109.475 26.32 109.525 ;
		RECT	0.32 109.935 26 110.105 ;
		RECT	0 109.935 0.32 110.105 ;
		RECT	26 109.935 26.32 110.105 ;
		RECT	0.32 110.825 26 111.515 ;
		RECT	0 110.825 0.32 111.515 ;
		RECT	26 110.825 26.32 111.515 ;
		RECT	0.32 112.315 26 112.365 ;
		RECT	0 112.315 0.32 112.365 ;
		RECT	26 112.315 26.32 112.365 ;
		RECT	0.32 112.775 26 112.945 ;
		RECT	0 112.775 0.32 112.945 ;
		RECT	26 112.775 26.32 112.945 ;
		RECT	0.32 113.665 26 114.245 ;
		RECT	0 113.665 0.32 114.245 ;
		RECT	26 113.665 26.32 114.245 ;
		RECT	0.32 115.055 26 115.145 ;
		RECT	0 115.055 0.32 115.145 ;
		RECT	26 115.055 26.32 115.145 ;
		LAYER	VIA1 DESIGNRULEWIDTH 0.07 ;
		RECT	0 0 26.32 115.145 ;
		LAYER	VIA2 DESIGNRULEWIDTH 0.07 ;
		RECT	0 0 26.32 115.145 ;
		LAYER	VIA3 DESIGNRULEWIDTH 0.07 ;
		RECT	0 0 26.32 115.145 ;
	END

END rf64x64

END LIBRARY

